VERSION 5.8 ;
BUSBITCHARS "[]" ;
DIVIDERCHAR "/" ;
UNITS
    DATABASE MICRONS 1000 ;
END UNITS

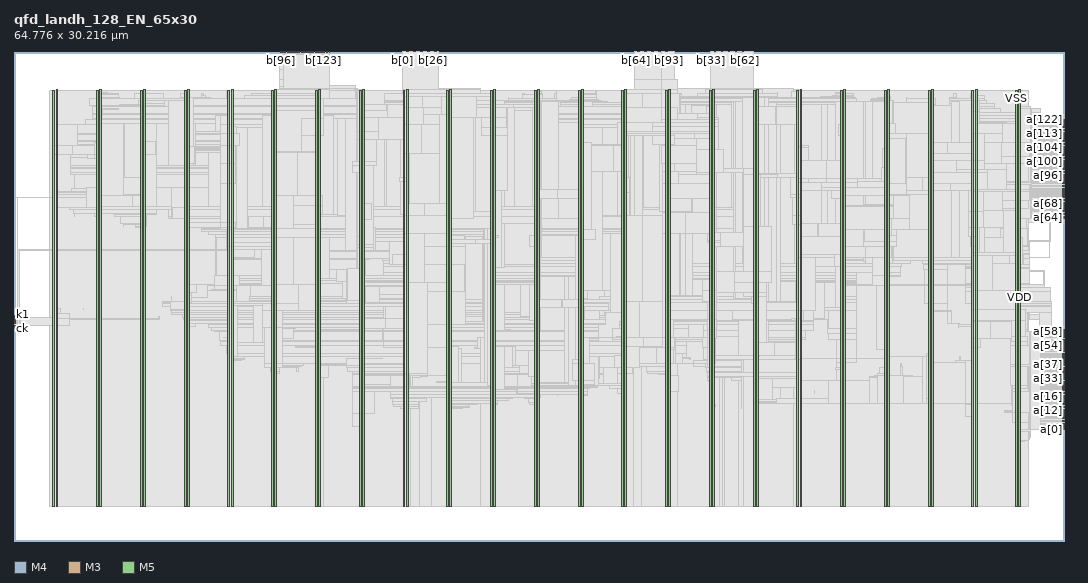
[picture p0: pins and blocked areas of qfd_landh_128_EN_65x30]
MACRO qfd_landh_128_EN_65x30
  FOREIGN qfd_landh_128_EN_65x30 0 0 ;
  CLASS BLOCK ;
  SIZE 64.776 BY 30.216 ;
  PIN a[0]
    DIRECTION INPUT ;
    USE SIGNAL ;
    PORT
      LAYER M4 ;
        RECT  64.692 6.864 64.776 6.888 ;
    END
  END a[0]
  PIN a[100]
    DIRECTION INPUT ;
    USE SIGNAL ;
    PORT
      LAYER M4 ;
        RECT  64.692 23.376 64.776 23.4 ;
    END
  END a[100]
  PIN a[101]
    DIRECTION INPUT ;
    USE SIGNAL ;
    PORT
      LAYER M4 ;
        RECT  64.692 23.472 64.776 23.496 ;
    END
  END a[101]
  PIN a[102]
    DIRECTION INPUT ;
    USE SIGNAL ;
    PORT
      LAYER M4 ;
        RECT  64.692 23.568 64.776 23.592 ;
    END
  END a[102]
  PIN a[103]
    DIRECTION INPUT ;
    USE SIGNAL ;
    PORT
      LAYER M4 ;
        RECT  64.692 23.664 64.776 23.688 ;
    END
  END a[103]
  PIN a[104]
    DIRECTION INPUT ;
    USE SIGNAL ;
    PORT
      LAYER M4 ;
        RECT  64.692 23.76 64.776 23.784 ;
    END
  END a[104]
  PIN a[105]
    DIRECTION INPUT ;
    USE SIGNAL ;
    PORT
      LAYER M4 ;
        RECT  64.692 23.856 64.776 23.88 ;
    END
  END a[105]
  PIN a[106]
    DIRECTION INPUT ;
    USE SIGNAL ;
    PORT
      LAYER M4 ;
        RECT  64.692 23.952 64.776 23.976 ;
    END
  END a[106]
  PIN a[107]
    DIRECTION INPUT ;
    USE SIGNAL ;
    PORT
      LAYER M4 ;
        RECT  64.692 24.048 64.776 24.072 ;
    END
  END a[107]
  PIN a[108]
    DIRECTION INPUT ;
    USE SIGNAL ;
    PORT
      LAYER M4 ;
        RECT  64.692 24.144 64.776 24.168 ;
    END
  END a[108]
  PIN a[109]
    DIRECTION INPUT ;
    USE SIGNAL ;
    PORT
      LAYER M4 ;
        RECT  64.692 24.24 64.776 24.264 ;
    END
  END a[109]
  PIN a[10]
    DIRECTION INPUT ;
    USE SIGNAL ;
    PORT
      LAYER M4 ;
        RECT  64.692 7.824 64.776 7.848 ;
    END
  END a[10]
  PIN a[110]
    DIRECTION INPUT ;
    USE SIGNAL ;
    PORT
      LAYER M4 ;
        RECT  64.692 24.336 64.776 24.36 ;
    END
  END a[110]
  PIN a[111]
    DIRECTION INPUT ;
    USE SIGNAL ;
    PORT
      LAYER M4 ;
        RECT  64.692 24.432 64.776 24.456 ;
    END
  END a[111]
  PIN a[112]
    DIRECTION INPUT ;
    USE SIGNAL ;
    PORT
      LAYER M4 ;
        RECT  64.692 24.528 64.776 24.552 ;
    END
  END a[112]
  PIN a[113]
    DIRECTION INPUT ;
    USE SIGNAL ;
    PORT
      LAYER M4 ;
        RECT  64.692 24.624 64.776 24.648 ;
    END
  END a[113]
  PIN a[114]
    DIRECTION INPUT ;
    USE SIGNAL ;
    PORT
      LAYER M4 ;
        RECT  64.692 24.72 64.776 24.744 ;
    END
  END a[114]
  PIN a[115]
    DIRECTION INPUT ;
    USE SIGNAL ;
    PORT
      LAYER M4 ;
        RECT  64.692 24.816 64.776 24.84 ;
    END
  END a[115]
  PIN a[116]
    DIRECTION INPUT ;
    USE SIGNAL ;
    PORT
      LAYER M4 ;
        RECT  64.692 24.912 64.776 24.936 ;
    END
  END a[116]
  PIN a[117]
    DIRECTION INPUT ;
    USE SIGNAL ;
    PORT
      LAYER M4 ;
        RECT  64.692 25.008 64.776 25.032 ;
    END
  END a[117]
  PIN a[118]
    DIRECTION INPUT ;
    USE SIGNAL ;
    PORT
      LAYER M4 ;
        RECT  64.692 25.104 64.776 25.128 ;
    END
  END a[118]
  PIN a[119]
    DIRECTION INPUT ;
    USE SIGNAL ;
    PORT
      LAYER M4 ;
        RECT  64.692 25.2 64.776 25.224 ;
    END
  END a[119]
  PIN a[11]
    DIRECTION INPUT ;
    USE SIGNAL ;
    PORT
      LAYER M4 ;
        RECT  64.692 7.92 64.776 7.944 ;
    END
  END a[11]
  PIN a[120]
    DIRECTION INPUT ;
    USE SIGNAL ;
    PORT
      LAYER M4 ;
        RECT  64.692 25.296 64.776 25.32 ;
    END
  END a[120]
  PIN a[121]
    DIRECTION INPUT ;
    USE SIGNAL ;
    PORT
      LAYER M4 ;
        RECT  64.692 25.392 64.776 25.416 ;
    END
  END a[121]
  PIN a[122]
    DIRECTION INPUT ;
    USE SIGNAL ;
    PORT
      LAYER M4 ;
        RECT  64.692 25.488 64.776 25.512 ;
    END
  END a[122]
  PIN a[123]
    DIRECTION INPUT ;
    USE SIGNAL ;
    PORT
      LAYER M4 ;
        RECT  64.692 25.584 64.776 25.608 ;
    END
  END a[123]
  PIN a[124]
    DIRECTION INPUT ;
    USE SIGNAL ;
    PORT
      LAYER M4 ;
        RECT  64.692 25.68 64.776 25.704 ;
    END
  END a[124]
  PIN a[125]
    DIRECTION INPUT ;
    USE SIGNAL ;
    PORT
      LAYER M4 ;
        RECT  64.692 25.776 64.776 25.8 ;
    END
  END a[125]
  PIN a[126]
    DIRECTION INPUT ;
    USE SIGNAL ;
    PORT
      LAYER M4 ;
        RECT  64.692 25.872 64.776 25.896 ;
    END
  END a[126]
  PIN a[127]
    DIRECTION INPUT ;
    USE SIGNAL ;
    PORT
      LAYER M4 ;
        RECT  64.692 25.968 64.776 25.992 ;
    END
  END a[127]
  PIN a[12]
    DIRECTION INPUT ;
    USE SIGNAL ;
    PORT
      LAYER M4 ;
        RECT  64.692 8.016 64.776 8.04 ;
    END
  END a[12]
  PIN a[13]
    DIRECTION INPUT ;
    USE SIGNAL ;
    PORT
      LAYER M4 ;
        RECT  64.692 8.112 64.776 8.136 ;
    END
  END a[13]
  PIN a[14]
    DIRECTION INPUT ;
    USE SIGNAL ;
    PORT
      LAYER M4 ;
        RECT  64.692 8.208 64.776 8.232 ;
    END
  END a[14]
  PIN a[15]
    DIRECTION INPUT ;
    USE SIGNAL ;
    PORT
      LAYER M4 ;
        RECT  64.692 8.304 64.776 8.328 ;
    END
  END a[15]
  PIN a[16]
    DIRECTION INPUT ;
    USE SIGNAL ;
    PORT
      LAYER M4 ;
        RECT  64.692 8.4 64.776 8.424 ;
    END
  END a[16]
  PIN a[17]
    DIRECTION INPUT ;
    USE SIGNAL ;
    PORT
      LAYER M4 ;
        RECT  64.692 8.496 64.776 8.52 ;
    END
  END a[17]
  PIN a[18]
    DIRECTION INPUT ;
    USE SIGNAL ;
    PORT
      LAYER M4 ;
        RECT  64.692 8.592 64.776 8.616 ;
    END
  END a[18]
  PIN a[19]
    DIRECTION INPUT ;
    USE SIGNAL ;
    PORT
      LAYER M4 ;
        RECT  64.692 8.688 64.776 8.712 ;
    END
  END a[19]
  PIN a[1]
    DIRECTION INPUT ;
    USE SIGNAL ;
    PORT
      LAYER M4 ;
        RECT  64.692 6.96 64.776 6.984 ;
    END
  END a[1]
  PIN a[20]
    DIRECTION INPUT ;
    USE SIGNAL ;
    PORT
      LAYER M4 ;
        RECT  64.692 8.784 64.776 8.808 ;
    END
  END a[20]
  PIN a[21]
    DIRECTION INPUT ;
    USE SIGNAL ;
    PORT
      LAYER M4 ;
        RECT  64.692 8.88 64.776 8.904 ;
    END
  END a[21]
  PIN a[22]
    DIRECTION INPUT ;
    USE SIGNAL ;
    PORT
      LAYER M4 ;
        RECT  64.692 8.976 64.776 9 ;
    END
  END a[22]
  PIN a[23]
    DIRECTION INPUT ;
    USE SIGNAL ;
    PORT
      LAYER M4 ;
        RECT  64.692 9.072 64.776 9.096 ;
    END
  END a[23]
  PIN a[24]
    DIRECTION INPUT ;
    USE SIGNAL ;
    PORT
      LAYER M4 ;
        RECT  64.692 9.168 64.776 9.192 ;
    END
  END a[24]
  PIN a[25]
    DIRECTION INPUT ;
    USE SIGNAL ;
    PORT
      LAYER M4 ;
        RECT  64.692 9.264 64.776 9.288 ;
    END
  END a[25]
  PIN a[26]
    DIRECTION INPUT ;
    USE SIGNAL ;
    PORT
      LAYER M4 ;
        RECT  64.692 9.36 64.776 9.384 ;
    END
  END a[26]
  PIN a[27]
    DIRECTION INPUT ;
    USE SIGNAL ;
    PORT
      LAYER M4 ;
        RECT  64.692 9.456 64.776 9.48 ;
    END
  END a[27]
  PIN a[28]
    DIRECTION INPUT ;
    USE SIGNAL ;
    PORT
      LAYER M4 ;
        RECT  64.692 9.552 64.776 9.576 ;
    END
  END a[28]
  PIN a[29]
    DIRECTION INPUT ;
    USE SIGNAL ;
    PORT
      LAYER M4 ;
        RECT  64.692 9.648 64.776 9.672 ;
    END
  END a[29]
  PIN a[2]
    DIRECTION INPUT ;
    USE SIGNAL ;
    PORT
      LAYER M4 ;
        RECT  64.692 7.056 64.776 7.08 ;
    END
  END a[2]
  PIN a[30]
    DIRECTION INPUT ;
    USE SIGNAL ;
    PORT
      LAYER M4 ;
        RECT  64.692 9.744 64.776 9.768 ;
    END
  END a[30]
  PIN a[31]
    DIRECTION INPUT ;
    USE SIGNAL ;
    PORT
      LAYER M4 ;
        RECT  64.692 9.84 64.776 9.864 ;
    END
  END a[31]
  PIN a[32]
    DIRECTION INPUT ;
    USE SIGNAL ;
    PORT
      LAYER M4 ;
        RECT  64.692 9.936 64.776 9.96 ;
    END
  END a[32]
  PIN a[33]
    DIRECTION INPUT ;
    USE SIGNAL ;
    PORT
      LAYER M4 ;
        RECT  64.692 10.032 64.776 10.056 ;
    END
  END a[33]
  PIN a[34]
    DIRECTION INPUT ;
    USE SIGNAL ;
    PORT
      LAYER M4 ;
        RECT  64.692 10.128 64.776 10.152 ;
    END
  END a[34]
  PIN a[35]
    DIRECTION INPUT ;
    USE SIGNAL ;
    PORT
      LAYER M4 ;
        RECT  64.692 10.224 64.776 10.248 ;
    END
  END a[35]
  PIN a[36]
    DIRECTION INPUT ;
    USE SIGNAL ;
    PORT
      LAYER M4 ;
        RECT  64.692 10.32 64.776 10.344 ;
    END
  END a[36]
  PIN a[37]
    DIRECTION INPUT ;
    USE SIGNAL ;
    PORT
      LAYER M4 ;
        RECT  64.692 10.416 64.776 10.44 ;
    END
  END a[37]
  PIN a[38]
    DIRECTION INPUT ;
    USE SIGNAL ;
    PORT
      LAYER M4 ;
        RECT  64.692 10.512 64.776 10.536 ;
    END
  END a[38]
  PIN a[39]
    DIRECTION INPUT ;
    USE SIGNAL ;
    PORT
      LAYER M4 ;
        RECT  64.692 10.608 64.776 10.632 ;
    END
  END a[39]
  PIN a[3]
    DIRECTION INPUT ;
    USE SIGNAL ;
    PORT
      LAYER M4 ;
        RECT  64.692 7.152 64.776 7.176 ;
    END
  END a[3]
  PIN a[40]
    DIRECTION INPUT ;
    USE SIGNAL ;
    PORT
      LAYER M4 ;
        RECT  64.692 10.704 64.776 10.728 ;
    END
  END a[40]
  PIN a[41]
    DIRECTION INPUT ;
    USE SIGNAL ;
    PORT
      LAYER M4 ;
        RECT  64.692 10.8 64.776 10.824 ;
    END
  END a[41]
  PIN a[42]
    DIRECTION INPUT ;
    USE SIGNAL ;
    PORT
      LAYER M4 ;
        RECT  64.692 10.896 64.776 10.92 ;
    END
  END a[42]
  PIN a[43]
    DIRECTION INPUT ;
    USE SIGNAL ;
    PORT
      LAYER M4 ;
        RECT  64.692 10.992 64.776 11.016 ;
    END
  END a[43]
  PIN a[44]
    DIRECTION INPUT ;
    USE SIGNAL ;
    PORT
      LAYER M4 ;
        RECT  64.692 11.088 64.776 11.112 ;
    END
  END a[44]
  PIN a[45]
    DIRECTION INPUT ;
    USE SIGNAL ;
    PORT
      LAYER M4 ;
        RECT  64.692 11.184 64.776 11.208 ;
    END
  END a[45]
  PIN a[46]
    DIRECTION INPUT ;
    USE SIGNAL ;
    PORT
      LAYER M4 ;
        RECT  64.692 11.28 64.776 11.304 ;
    END
  END a[46]
  PIN a[47]
    DIRECTION INPUT ;
    USE SIGNAL ;
    PORT
      LAYER M4 ;
        RECT  64.692 11.376 64.776 11.4 ;
    END
  END a[47]
  PIN a[48]
    DIRECTION INPUT ;
    USE SIGNAL ;
    PORT
      LAYER M4 ;
        RECT  64.692 11.472 64.776 11.496 ;
    END
  END a[48]
  PIN a[49]
    DIRECTION INPUT ;
    USE SIGNAL ;
    PORT
      LAYER M4 ;
        RECT  64.692 11.568 64.776 11.592 ;
    END
  END a[49]
  PIN a[4]
    DIRECTION INPUT ;
    USE SIGNAL ;
    PORT
      LAYER M4 ;
        RECT  64.692 7.248 64.776 7.272 ;
    END
  END a[4]
  PIN a[50]
    DIRECTION INPUT ;
    USE SIGNAL ;
    PORT
      LAYER M4 ;
        RECT  64.692 11.664 64.776 11.688 ;
    END
  END a[50]
  PIN a[51]
    DIRECTION INPUT ;
    USE SIGNAL ;
    PORT
      LAYER M4 ;
        RECT  64.692 11.76 64.776 11.784 ;
    END
  END a[51]
  PIN a[52]
    DIRECTION INPUT ;
    USE SIGNAL ;
    PORT
      LAYER M4 ;
        RECT  64.692 11.856 64.776 11.88 ;
    END
  END a[52]
  PIN a[53]
    DIRECTION INPUT ;
    USE SIGNAL ;
    PORT
      LAYER M4 ;
        RECT  64.692 11.952 64.776 11.976 ;
    END
  END a[53]
  PIN a[54]
    DIRECTION INPUT ;
    USE SIGNAL ;
    PORT
      LAYER M4 ;
        RECT  64.692 12.048 64.776 12.072 ;
    END
  END a[54]
  PIN a[55]
    DIRECTION INPUT ;
    USE SIGNAL ;
    PORT
      LAYER M4 ;
        RECT  64.692 12.144 64.776 12.168 ;
    END
  END a[55]
  PIN a[56]
    DIRECTION INPUT ;
    USE SIGNAL ;
    PORT
      LAYER M4 ;
        RECT  64.692 12.24 64.776 12.264 ;
    END
  END a[56]
  PIN a[57]
    DIRECTION INPUT ;
    USE SIGNAL ;
    PORT
      LAYER M4 ;
        RECT  64.692 12.336 64.776 12.36 ;
    END
  END a[57]
  PIN a[58]
    DIRECTION INPUT ;
    USE SIGNAL ;
    PORT
      LAYER M4 ;
        RECT  64.692 12.432 64.776 12.456 ;
    END
  END a[58]
  PIN a[59]
    DIRECTION INPUT ;
    USE SIGNAL ;
    PORT
      LAYER M4 ;
        RECT  64.692 12.528 64.776 12.552 ;
    END
  END a[59]
  PIN a[5]
    DIRECTION INPUT ;
    USE SIGNAL ;
    PORT
      LAYER M4 ;
        RECT  64.692 7.344 64.776 7.368 ;
    END
  END a[5]
  PIN a[60]
    DIRECTION INPUT ;
    USE SIGNAL ;
    PORT
      LAYER M4 ;
        RECT  64.692 12.624 64.776 12.648 ;
    END
  END a[60]
  PIN a[61]
    DIRECTION INPUT ;
    USE SIGNAL ;
    PORT
      LAYER M4 ;
        RECT  64.692 12.72 64.776 12.744 ;
    END
  END a[61]
  PIN a[62]
    DIRECTION INPUT ;
    USE SIGNAL ;
    PORT
      LAYER M4 ;
        RECT  64.692 12.816 64.776 12.84 ;
    END
  END a[62]
  PIN a[63]
    DIRECTION INPUT ;
    USE SIGNAL ;
    PORT
      LAYER M4 ;
        RECT  64.692 12.912 64.776 12.936 ;
    END
  END a[63]
  PIN a[64]
    DIRECTION INPUT ;
    USE SIGNAL ;
    PORT
      LAYER M4 ;
        RECT  64.692 19.92 64.776 19.944 ;
    END
  END a[64]
  PIN a[65]
    DIRECTION INPUT ;
    USE SIGNAL ;
    PORT
      LAYER M4 ;
        RECT  64.692 20.016 64.776 20.04 ;
    END
  END a[65]
  PIN a[66]
    DIRECTION INPUT ;
    USE SIGNAL ;
    PORT
      LAYER M4 ;
        RECT  64.692 20.112 64.776 20.136 ;
    END
  END a[66]
  PIN a[67]
    DIRECTION INPUT ;
    USE SIGNAL ;
    PORT
      LAYER M4 ;
        RECT  64.692 20.208 64.776 20.232 ;
    END
  END a[67]
  PIN a[68]
    DIRECTION INPUT ;
    USE SIGNAL ;
    PORT
      LAYER M4 ;
        RECT  64.692 20.304 64.776 20.328 ;
    END
  END a[68]
  PIN a[69]
    DIRECTION INPUT ;
    USE SIGNAL ;
    PORT
      LAYER M4 ;
        RECT  64.692 20.4 64.776 20.424 ;
    END
  END a[69]
  PIN a[6]
    DIRECTION INPUT ;
    USE SIGNAL ;
    PORT
      LAYER M4 ;
        RECT  64.692 7.44 64.776 7.464 ;
    END
  END a[6]
  PIN a[70]
    DIRECTION INPUT ;
    USE SIGNAL ;
    PORT
      LAYER M4 ;
        RECT  64.692 20.496 64.776 20.52 ;
    END
  END a[70]
  PIN a[71]
    DIRECTION INPUT ;
    USE SIGNAL ;
    PORT
      LAYER M4 ;
        RECT  64.692 20.592 64.776 20.616 ;
    END
  END a[71]
  PIN a[72]
    DIRECTION INPUT ;
    USE SIGNAL ;
    PORT
      LAYER M4 ;
        RECT  64.692 20.688 64.776 20.712 ;
    END
  END a[72]
  PIN a[73]
    DIRECTION INPUT ;
    USE SIGNAL ;
    PORT
      LAYER M4 ;
        RECT  64.692 20.784 64.776 20.808 ;
    END
  END a[73]
  PIN a[74]
    DIRECTION INPUT ;
    USE SIGNAL ;
    PORT
      LAYER M4 ;
        RECT  64.692 20.88 64.776 20.904 ;
    END
  END a[74]
  PIN a[75]
    DIRECTION INPUT ;
    USE SIGNAL ;
    PORT
      LAYER M4 ;
        RECT  64.692 20.976 64.776 21 ;
    END
  END a[75]
  PIN a[76]
    DIRECTION INPUT ;
    USE SIGNAL ;
    PORT
      LAYER M4 ;
        RECT  64.692 21.072 64.776 21.096 ;
    END
  END a[76]
  PIN a[77]
    DIRECTION INPUT ;
    USE SIGNAL ;
    PORT
      LAYER M4 ;
        RECT  64.692 21.168 64.776 21.192 ;
    END
  END a[77]
  PIN a[78]
    DIRECTION INPUT ;
    USE SIGNAL ;
    PORT
      LAYER M4 ;
        RECT  64.692 21.264 64.776 21.288 ;
    END
  END a[78]
  PIN a[79]
    DIRECTION INPUT ;
    USE SIGNAL ;
    PORT
      LAYER M4 ;
        RECT  64.692 21.36 64.776 21.384 ;
    END
  END a[79]
  PIN a[7]
    DIRECTION INPUT ;
    USE SIGNAL ;
    PORT
      LAYER M4 ;
        RECT  64.692 7.536 64.776 7.56 ;
    END
  END a[7]
  PIN a[80]
    DIRECTION INPUT ;
    USE SIGNAL ;
    PORT
      LAYER M4 ;
        RECT  64.692 21.456 64.776 21.48 ;
    END
  END a[80]
  PIN a[81]
    DIRECTION INPUT ;
    USE SIGNAL ;
    PORT
      LAYER M4 ;
        RECT  64.692 21.552 64.776 21.576 ;
    END
  END a[81]
  PIN a[82]
    DIRECTION INPUT ;
    USE SIGNAL ;
    PORT
      LAYER M4 ;
        RECT  64.692 21.648 64.776 21.672 ;
    END
  END a[82]
  PIN a[83]
    DIRECTION INPUT ;
    USE SIGNAL ;
    PORT
      LAYER M4 ;
        RECT  64.692 21.744 64.776 21.768 ;
    END
  END a[83]
  PIN a[84]
    DIRECTION INPUT ;
    USE SIGNAL ;
    PORT
      LAYER M4 ;
        RECT  64.692 21.84 64.776 21.864 ;
    END
  END a[84]
  PIN a[85]
    DIRECTION INPUT ;
    USE SIGNAL ;
    PORT
      LAYER M4 ;
        RECT  64.692 21.936 64.776 21.96 ;
    END
  END a[85]
  PIN a[86]
    DIRECTION INPUT ;
    USE SIGNAL ;
    PORT
      LAYER M4 ;
        RECT  64.692 22.032 64.776 22.056 ;
    END
  END a[86]
  PIN a[87]
    DIRECTION INPUT ;
    USE SIGNAL ;
    PORT
      LAYER M4 ;
        RECT  64.692 22.128 64.776 22.152 ;
    END
  END a[87]
  PIN a[88]
    DIRECTION INPUT ;
    USE SIGNAL ;
    PORT
      LAYER M4 ;
        RECT  64.692 22.224 64.776 22.248 ;
    END
  END a[88]
  PIN a[89]
    DIRECTION INPUT ;
    USE SIGNAL ;
    PORT
      LAYER M4 ;
        RECT  64.692 22.32 64.776 22.344 ;
    END
  END a[89]
  PIN a[8]
    DIRECTION INPUT ;
    USE SIGNAL ;
    PORT
      LAYER M4 ;
        RECT  64.692 7.632 64.776 7.656 ;
    END
  END a[8]
  PIN a[90]
    DIRECTION INPUT ;
    USE SIGNAL ;
    PORT
      LAYER M4 ;
        RECT  64.692 22.416 64.776 22.44 ;
    END
  END a[90]
  PIN a[91]
    DIRECTION INPUT ;
    USE SIGNAL ;
    PORT
      LAYER M4 ;
        RECT  64.692 22.512 64.776 22.536 ;
    END
  END a[91]
  PIN a[92]
    DIRECTION INPUT ;
    USE SIGNAL ;
    PORT
      LAYER M4 ;
        RECT  64.692 22.608 64.776 22.632 ;
    END
  END a[92]
  PIN a[93]
    DIRECTION INPUT ;
    USE SIGNAL ;
    PORT
      LAYER M4 ;
        RECT  64.692 22.704 64.776 22.728 ;
    END
  END a[93]
  PIN a[94]
    DIRECTION INPUT ;
    USE SIGNAL ;
    PORT
      LAYER M4 ;
        RECT  64.692 22.8 64.776 22.824 ;
    END
  END a[94]
  PIN a[95]
    DIRECTION INPUT ;
    USE SIGNAL ;
    PORT
      LAYER M4 ;
        RECT  64.692 22.896 64.776 22.92 ;
    END
  END a[95]
  PIN a[96]
    DIRECTION INPUT ;
    USE SIGNAL ;
    PORT
      LAYER M4 ;
        RECT  64.692 22.992 64.776 23.016 ;
    END
  END a[96]
  PIN a[97]
    DIRECTION INPUT ;
    USE SIGNAL ;
    PORT
      LAYER M4 ;
        RECT  64.692 23.088 64.776 23.112 ;
    END
  END a[97]
  PIN a[98]
    DIRECTION INPUT ;
    USE SIGNAL ;
    PORT
      LAYER M4 ;
        RECT  64.692 23.184 64.776 23.208 ;
    END
  END a[98]
  PIN a[99]
    DIRECTION INPUT ;
    USE SIGNAL ;
    PORT
      LAYER M4 ;
        RECT  64.692 23.28 64.776 23.304 ;
    END
  END a[99]
  PIN a[9]
    DIRECTION INPUT ;
    USE SIGNAL ;
    PORT
      LAYER M4 ;
        RECT  64.692 7.728 64.776 7.752 ;
    END
  END a[9]
  PIN b[0]
    DIRECTION OUTPUT ;
    USE SIGNAL ;
    PORT
      LAYER M3 ;
        RECT  23.94 30.179 23.958 30.216 ;
    END
  END b[0]
  PIN b[100]
    DIRECTION OUTPUT ;
    USE SIGNAL ;
    PORT
      LAYER M5 ;
        RECT  16.848 30.132 16.872 30.216 ;
    END
  END b[100]
  PIN b[101]
    DIRECTION OUTPUT ;
    USE SIGNAL ;
    PORT
      LAYER M5 ;
        RECT  16.944 30.132 16.968 30.216 ;
    END
  END b[101]
  PIN b[102]
    DIRECTION OUTPUT ;
    USE SIGNAL ;
    PORT
      LAYER M5 ;
        RECT  17.04 30.132 17.064 30.216 ;
    END
  END b[102]
  PIN b[103]
    DIRECTION OUTPUT ;
    USE SIGNAL ;
    PORT
      LAYER M5 ;
        RECT  17.136 30.132 17.16 30.216 ;
    END
  END b[103]
  PIN b[104]
    DIRECTION OUTPUT ;
    USE SIGNAL ;
    PORT
      LAYER M5 ;
        RECT  17.232 30.132 17.256 30.216 ;
    END
  END b[104]
  PIN b[105]
    DIRECTION OUTPUT ;
    USE SIGNAL ;
    PORT
      LAYER M5 ;
        RECT  17.328 30.132 17.352 30.216 ;
    END
  END b[105]
  PIN b[106]
    DIRECTION OUTPUT ;
    USE SIGNAL ;
    PORT
      LAYER M5 ;
        RECT  17.424 30.132 17.448 30.216 ;
    END
  END b[106]
  PIN b[107]
    DIRECTION OUTPUT ;
    USE SIGNAL ;
    PORT
      LAYER M5 ;
        RECT  17.52 30.132 17.544 30.216 ;
    END
  END b[107]
  PIN b[108]
    DIRECTION OUTPUT ;
    USE SIGNAL ;
    PORT
      LAYER M5 ;
        RECT  17.616 30.132 17.64 30.216 ;
    END
  END b[108]
  PIN b[109]
    DIRECTION OUTPUT ;
    USE SIGNAL ;
    PORT
      LAYER M5 ;
        RECT  17.712 30.132 17.736 30.216 ;
    END
  END b[109]
  PIN b[10]
    DIRECTION OUTPUT ;
    USE SIGNAL ;
    PORT
      LAYER M3 ;
        RECT  24.66 30.179 24.678 30.216 ;
    END
  END b[10]
  PIN b[110]
    DIRECTION OUTPUT ;
    USE SIGNAL ;
    PORT
      LAYER M5 ;
        RECT  17.808 30.132 17.832 30.216 ;
    END
  END b[110]
  PIN b[111]
    DIRECTION OUTPUT ;
    USE SIGNAL ;
    PORT
      LAYER M5 ;
        RECT  17.904 30.132 17.928 30.216 ;
    END
  END b[111]
  PIN b[112]
    DIRECTION OUTPUT ;
    USE SIGNAL ;
    PORT
      LAYER M5 ;
        RECT  18 30.132 18.024 30.216 ;
    END
  END b[112]
  PIN b[113]
    DIRECTION OUTPUT ;
    USE SIGNAL ;
    PORT
      LAYER M5 ;
        RECT  18.096 30.132 18.12 30.216 ;
    END
  END b[113]
  PIN b[114]
    DIRECTION OUTPUT ;
    USE SIGNAL ;
    PORT
      LAYER M5 ;
        RECT  18.192 30.132 18.216 30.216 ;
    END
  END b[114]
  PIN b[115]
    DIRECTION OUTPUT ;
    USE SIGNAL ;
    PORT
      LAYER M5 ;
        RECT  18.288 30.132 18.312 30.216 ;
    END
  END b[115]
  PIN b[116]
    DIRECTION OUTPUT ;
    USE SIGNAL ;
    PORT
      LAYER M5 ;
        RECT  18.384 30.132 18.408 30.216 ;
    END
  END b[116]
  PIN b[117]
    DIRECTION OUTPUT ;
    USE SIGNAL ;
    PORT
      LAYER M5 ;
        RECT  18.48 30.132 18.504 30.216 ;
    END
  END b[117]
  PIN b[118]
    DIRECTION OUTPUT ;
    USE SIGNAL ;
    PORT
      LAYER M5 ;
        RECT  18.576 30.132 18.6 30.216 ;
    END
  END b[118]
  PIN b[119]
    DIRECTION OUTPUT ;
    USE SIGNAL ;
    PORT
      LAYER M5 ;
        RECT  18.672 30.132 18.696 30.216 ;
    END
  END b[119]
  PIN b[11]
    DIRECTION OUTPUT ;
    USE SIGNAL ;
    PORT
      LAYER M3 ;
        RECT  24.732 30.179 24.75 30.216 ;
    END
  END b[11]
  PIN b[120]
    DIRECTION OUTPUT ;
    USE SIGNAL ;
    PORT
      LAYER M5 ;
        RECT  18.768 30.132 18.792 30.216 ;
    END
  END b[120]
  PIN b[121]
    DIRECTION OUTPUT ;
    USE SIGNAL ;
    PORT
      LAYER M5 ;
        RECT  18.864 30.132 18.888 30.216 ;
    END
  END b[121]
  PIN b[122]
    DIRECTION OUTPUT ;
    USE SIGNAL ;
    PORT
      LAYER M5 ;
        RECT  18.96 30.132 18.984 30.216 ;
    END
  END b[122]
  PIN b[123]
    DIRECTION OUTPUT ;
    USE SIGNAL ;
    PORT
      LAYER M5 ;
        RECT  19.056 30.132 19.08 30.216 ;
    END
  END b[123]
  PIN b[124]
    DIRECTION OUTPUT ;
    USE SIGNAL ;
    PORT
      LAYER M5 ;
        RECT  19.152 30.132 19.176 30.216 ;
    END
  END b[124]
  PIN b[125]
    DIRECTION OUTPUT ;
    USE SIGNAL ;
    PORT
      LAYER M5 ;
        RECT  19.248 30.132 19.272 30.216 ;
    END
  END b[125]
  PIN b[126]
    DIRECTION OUTPUT ;
    USE SIGNAL ;
    PORT
      LAYER M5 ;
        RECT  19.344 30.132 19.368 30.216 ;
    END
  END b[126]
  PIN b[127]
    DIRECTION OUTPUT ;
    USE SIGNAL ;
    PORT
      LAYER M5 ;
        RECT  19.44 30.132 19.464 30.216 ;
    END
  END b[127]
  PIN b[12]
    DIRECTION OUTPUT ;
    USE SIGNAL ;
    PORT
      LAYER M3 ;
        RECT  24.804 30.179 24.822 30.216 ;
    END
  END b[12]
  PIN b[13]
    DIRECTION OUTPUT ;
    USE SIGNAL ;
    PORT
      LAYER M3 ;
        RECT  24.876 30.179 24.894 30.216 ;
    END
  END b[13]
  PIN b[14]
    DIRECTION OUTPUT ;
    USE SIGNAL ;
    PORT
      LAYER M3 ;
        RECT  24.948 30.179 24.966 30.216 ;
    END
  END b[14]
  PIN b[15]
    DIRECTION OUTPUT ;
    USE SIGNAL ;
    PORT
      LAYER M3 ;
        RECT  25.02 30.179 25.038 30.216 ;
    END
  END b[15]
  PIN b[16]
    DIRECTION OUTPUT ;
    USE SIGNAL ;
    PORT
      LAYER M3 ;
        RECT  25.092 30.179 25.11 30.216 ;
    END
  END b[16]
  PIN b[17]
    DIRECTION OUTPUT ;
    USE SIGNAL ;
    PORT
      LAYER M3 ;
        RECT  25.164 30.179 25.182 30.216 ;
    END
  END b[17]
  PIN b[18]
    DIRECTION OUTPUT ;
    USE SIGNAL ;
    PORT
      LAYER M3 ;
        RECT  25.236 30.179 25.254 30.216 ;
    END
  END b[18]
  PIN b[19]
    DIRECTION OUTPUT ;
    USE SIGNAL ;
    PORT
      LAYER M3 ;
        RECT  25.308 30.179 25.326 30.216 ;
    END
  END b[19]
  PIN b[1]
    DIRECTION OUTPUT ;
    USE SIGNAL ;
    PORT
      LAYER M3 ;
        RECT  24.012 30.179 24.03 30.216 ;
    END
  END b[1]
  PIN b[20]
    DIRECTION OUTPUT ;
    USE SIGNAL ;
    PORT
      LAYER M3 ;
        RECT  25.38 30.179 25.398 30.216 ;
    END
  END b[20]
  PIN b[21]
    DIRECTION OUTPUT ;
    USE SIGNAL ;
    PORT
      LAYER M3 ;
        RECT  25.452 30.179 25.47 30.216 ;
    END
  END b[21]
  PIN b[22]
    DIRECTION OUTPUT ;
    USE SIGNAL ;
    PORT
      LAYER M3 ;
        RECT  25.524 30.179 25.542 30.216 ;
    END
  END b[22]
  PIN b[23]
    DIRECTION OUTPUT ;
    USE SIGNAL ;
    PORT
      LAYER M3 ;
        RECT  25.596 30.179 25.614 30.216 ;
    END
  END b[23]
  PIN b[24]
    DIRECTION OUTPUT ;
    USE SIGNAL ;
    PORT
      LAYER M3 ;
        RECT  25.668 30.179 25.686 30.216 ;
    END
  END b[24]
  PIN b[25]
    DIRECTION OUTPUT ;
    USE SIGNAL ;
    PORT
      LAYER M3 ;
        RECT  25.74 30.179 25.758 30.216 ;
    END
  END b[25]
  PIN b[26]
    DIRECTION OUTPUT ;
    USE SIGNAL ;
    PORT
      LAYER M3 ;
        RECT  25.812 30.179 25.83 30.216 ;
    END
  END b[26]
  PIN b[27]
    DIRECTION OUTPUT ;
    USE SIGNAL ;
    PORT
      LAYER M3 ;
        RECT  25.884 30.179 25.902 30.216 ;
    END
  END b[27]
  PIN b[28]
    DIRECTION OUTPUT ;
    USE SIGNAL ;
    PORT
      LAYER M3 ;
        RECT  25.956 30.179 25.974 30.216 ;
    END
  END b[28]
  PIN b[29]
    DIRECTION OUTPUT ;
    USE SIGNAL ;
    PORT
      LAYER M3 ;
        RECT  26.028 30.179 26.046 30.216 ;
    END
  END b[29]
  PIN b[2]
    DIRECTION OUTPUT ;
    USE SIGNAL ;
    PORT
      LAYER M3 ;
        RECT  24.084 30.179 24.102 30.216 ;
    END
  END b[2]
  PIN b[30]
    DIRECTION OUTPUT ;
    USE SIGNAL ;
    PORT
      LAYER M3 ;
        RECT  26.1 30.179 26.118 30.216 ;
    END
  END b[30]
  PIN b[31]
    DIRECTION OUTPUT ;
    USE SIGNAL ;
    PORT
      LAYER M3 ;
        RECT  26.172 30.179 26.19 30.216 ;
    END
  END b[31]
  PIN b[32]
    DIRECTION OUTPUT ;
    USE SIGNAL ;
    PORT
      LAYER M3 ;
        RECT  42.948 30.179 42.966 30.216 ;
    END
  END b[32]
  PIN b[33]
    DIRECTION OUTPUT ;
    USE SIGNAL ;
    PORT
      LAYER M3 ;
        RECT  43.02 30.179 43.038 30.216 ;
    END
  END b[33]
  PIN b[34]
    DIRECTION OUTPUT ;
    USE SIGNAL ;
    PORT
      LAYER M3 ;
        RECT  43.092 30.179 43.11 30.216 ;
    END
  END b[34]
  PIN b[35]
    DIRECTION OUTPUT ;
    USE SIGNAL ;
    PORT
      LAYER M3 ;
        RECT  43.164 30.179 43.182 30.216 ;
    END
  END b[35]
  PIN b[36]
    DIRECTION OUTPUT ;
    USE SIGNAL ;
    PORT
      LAYER M3 ;
        RECT  43.236 30.179 43.254 30.216 ;
    END
  END b[36]
  PIN b[37]
    DIRECTION OUTPUT ;
    USE SIGNAL ;
    PORT
      LAYER M3 ;
        RECT  43.308 30.179 43.326 30.216 ;
    END
  END b[37]
  PIN b[38]
    DIRECTION OUTPUT ;
    USE SIGNAL ;
    PORT
      LAYER M3 ;
        RECT  43.38 30.179 43.398 30.216 ;
    END
  END b[38]
  PIN b[39]
    DIRECTION OUTPUT ;
    USE SIGNAL ;
    PORT
      LAYER M3 ;
        RECT  43.452 30.179 43.47 30.216 ;
    END
  END b[39]
  PIN b[3]
    DIRECTION OUTPUT ;
    USE SIGNAL ;
    PORT
      LAYER M3 ;
        RECT  24.156 30.179 24.174 30.216 ;
    END
  END b[3]
  PIN b[40]
    DIRECTION OUTPUT ;
    USE SIGNAL ;
    PORT
      LAYER M3 ;
        RECT  43.524 30.179 43.542 30.216 ;
    END
  END b[40]
  PIN b[41]
    DIRECTION OUTPUT ;
    USE SIGNAL ;
    PORT
      LAYER M3 ;
        RECT  43.596 30.179 43.614 30.216 ;
    END
  END b[41]
  PIN b[42]
    DIRECTION OUTPUT ;
    USE SIGNAL ;
    PORT
      LAYER M3 ;
        RECT  43.668 30.179 43.686 30.216 ;
    END
  END b[42]
  PIN b[43]
    DIRECTION OUTPUT ;
    USE SIGNAL ;
    PORT
      LAYER M3 ;
        RECT  43.74 30.179 43.758 30.216 ;
    END
  END b[43]
  PIN b[44]
    DIRECTION OUTPUT ;
    USE SIGNAL ;
    PORT
      LAYER M3 ;
        RECT  43.812 30.179 43.83 30.216 ;
    END
  END b[44]
  PIN b[45]
    DIRECTION OUTPUT ;
    USE SIGNAL ;
    PORT
      LAYER M3 ;
        RECT  43.884 30.179 43.902 30.216 ;
    END
  END b[45]
  PIN b[46]
    DIRECTION OUTPUT ;
    USE SIGNAL ;
    PORT
      LAYER M3 ;
        RECT  43.956 30.179 43.974 30.216 ;
    END
  END b[46]
  PIN b[47]
    DIRECTION OUTPUT ;
    USE SIGNAL ;
    PORT
      LAYER M3 ;
        RECT  44.028 30.179 44.046 30.216 ;
    END
  END b[47]
  PIN b[48]
    DIRECTION OUTPUT ;
    USE SIGNAL ;
    PORT
      LAYER M3 ;
        RECT  44.1 30.179 44.118 30.216 ;
    END
  END b[48]
  PIN b[49]
    DIRECTION OUTPUT ;
    USE SIGNAL ;
    PORT
      LAYER M3 ;
        RECT  44.172 30.179 44.19 30.216 ;
    END
  END b[49]
  PIN b[4]
    DIRECTION OUTPUT ;
    USE SIGNAL ;
    PORT
      LAYER M3 ;
        RECT  24.228 30.179 24.246 30.216 ;
    END
  END b[4]
  PIN b[50]
    DIRECTION OUTPUT ;
    USE SIGNAL ;
    PORT
      LAYER M3 ;
        RECT  44.244 30.179 44.262 30.216 ;
    END
  END b[50]
  PIN b[51]
    DIRECTION OUTPUT ;
    USE SIGNAL ;
    PORT
      LAYER M3 ;
        RECT  44.316 30.179 44.334 30.216 ;
    END
  END b[51]
  PIN b[52]
    DIRECTION OUTPUT ;
    USE SIGNAL ;
    PORT
      LAYER M3 ;
        RECT  44.388 30.179 44.406 30.216 ;
    END
  END b[52]
  PIN b[53]
    DIRECTION OUTPUT ;
    USE SIGNAL ;
    PORT
      LAYER M3 ;
        RECT  44.46 30.179 44.478 30.216 ;
    END
  END b[53]
  PIN b[54]
    DIRECTION OUTPUT ;
    USE SIGNAL ;
    PORT
      LAYER M3 ;
        RECT  44.532 30.179 44.55 30.216 ;
    END
  END b[54]
  PIN b[55]
    DIRECTION OUTPUT ;
    USE SIGNAL ;
    PORT
      LAYER M3 ;
        RECT  44.604 30.179 44.622 30.216 ;
    END
  END b[55]
  PIN b[56]
    DIRECTION OUTPUT ;
    USE SIGNAL ;
    PORT
      LAYER M3 ;
        RECT  44.676 30.179 44.694 30.216 ;
    END
  END b[56]
  PIN b[57]
    DIRECTION OUTPUT ;
    USE SIGNAL ;
    PORT
      LAYER M3 ;
        RECT  44.748 30.179 44.766 30.216 ;
    END
  END b[57]
  PIN b[58]
    DIRECTION OUTPUT ;
    USE SIGNAL ;
    PORT
      LAYER M3 ;
        RECT  44.82 30.179 44.838 30.216 ;
    END
  END b[58]
  PIN b[59]
    DIRECTION OUTPUT ;
    USE SIGNAL ;
    PORT
      LAYER M3 ;
        RECT  44.892 30.179 44.91 30.216 ;
    END
  END b[59]
  PIN b[5]
    DIRECTION OUTPUT ;
    USE SIGNAL ;
    PORT
      LAYER M3 ;
        RECT  24.3 30.179 24.318 30.216 ;
    END
  END b[5]
  PIN b[60]
    DIRECTION OUTPUT ;
    USE SIGNAL ;
    PORT
      LAYER M3 ;
        RECT  44.964 30.179 44.982 30.216 ;
    END
  END b[60]
  PIN b[61]
    DIRECTION OUTPUT ;
    USE SIGNAL ;
    PORT
      LAYER M3 ;
        RECT  45.036 30.179 45.054 30.216 ;
    END
  END b[61]
  PIN b[62]
    DIRECTION OUTPUT ;
    USE SIGNAL ;
    PORT
      LAYER M3 ;
        RECT  45.108 30.179 45.126 30.216 ;
    END
  END b[62]
  PIN b[63]
    DIRECTION OUTPUT ;
    USE SIGNAL ;
    PORT
      LAYER M3 ;
        RECT  45.18 30.179 45.198 30.216 ;
    END
  END b[63]
  PIN b[64]
    DIRECTION OUTPUT ;
    USE SIGNAL ;
    PORT
      LAYER M3 ;
        RECT  38.34 30.179 38.358 30.216 ;
    END
  END b[64]
  PIN b[65]
    DIRECTION OUTPUT ;
    USE SIGNAL ;
    PORT
      LAYER M3 ;
        RECT  38.412 30.179 38.43 30.216 ;
    END
  END b[65]
  PIN b[66]
    DIRECTION OUTPUT ;
    USE SIGNAL ;
    PORT
      LAYER M3 ;
        RECT  38.484 30.179 38.502 30.216 ;
    END
  END b[66]
  PIN b[67]
    DIRECTION OUTPUT ;
    USE SIGNAL ;
    PORT
      LAYER M3 ;
        RECT  38.556 30.179 38.574 30.216 ;
    END
  END b[67]
  PIN b[68]
    DIRECTION OUTPUT ;
    USE SIGNAL ;
    PORT
      LAYER M3 ;
        RECT  38.628 30.179 38.646 30.216 ;
    END
  END b[68]
  PIN b[69]
    DIRECTION OUTPUT ;
    USE SIGNAL ;
    PORT
      LAYER M3 ;
        RECT  38.7 30.179 38.718 30.216 ;
    END
  END b[69]
  PIN b[6]
    DIRECTION OUTPUT ;
    USE SIGNAL ;
    PORT
      LAYER M3 ;
        RECT  24.372 30.179 24.39 30.216 ;
    END
  END b[6]
  PIN b[70]
    DIRECTION OUTPUT ;
    USE SIGNAL ;
    PORT
      LAYER M3 ;
        RECT  38.772 30.179 38.79 30.216 ;
    END
  END b[70]
  PIN b[71]
    DIRECTION OUTPUT ;
    USE SIGNAL ;
    PORT
      LAYER M3 ;
        RECT  38.844 30.179 38.862 30.216 ;
    END
  END b[71]
  PIN b[72]
    DIRECTION OUTPUT ;
    USE SIGNAL ;
    PORT
      LAYER M3 ;
        RECT  38.916 30.179 38.934 30.216 ;
    END
  END b[72]
  PIN b[73]
    DIRECTION OUTPUT ;
    USE SIGNAL ;
    PORT
      LAYER M3 ;
        RECT  38.988 30.179 39.006 30.216 ;
    END
  END b[73]
  PIN b[74]
    DIRECTION OUTPUT ;
    USE SIGNAL ;
    PORT
      LAYER M3 ;
        RECT  39.06 30.179 39.078 30.216 ;
    END
  END b[74]
  PIN b[75]
    DIRECTION OUTPUT ;
    USE SIGNAL ;
    PORT
      LAYER M3 ;
        RECT  39.132 30.179 39.15 30.216 ;
    END
  END b[75]
  PIN b[76]
    DIRECTION OUTPUT ;
    USE SIGNAL ;
    PORT
      LAYER M3 ;
        RECT  39.204 30.179 39.222 30.216 ;
    END
  END b[76]
  PIN b[77]
    DIRECTION OUTPUT ;
    USE SIGNAL ;
    PORT
      LAYER M3 ;
        RECT  39.276 30.179 39.294 30.216 ;
    END
  END b[77]
  PIN b[78]
    DIRECTION OUTPUT ;
    USE SIGNAL ;
    PORT
      LAYER M3 ;
        RECT  39.348 30.179 39.366 30.216 ;
    END
  END b[78]
  PIN b[79]
    DIRECTION OUTPUT ;
    USE SIGNAL ;
    PORT
      LAYER M3 ;
        RECT  39.42 30.179 39.438 30.216 ;
    END
  END b[79]
  PIN b[7]
    DIRECTION OUTPUT ;
    USE SIGNAL ;
    PORT
      LAYER M3 ;
        RECT  24.444 30.179 24.462 30.216 ;
    END
  END b[7]
  PIN b[80]
    DIRECTION OUTPUT ;
    USE SIGNAL ;
    PORT
      LAYER M3 ;
        RECT  39.492 30.179 39.51 30.216 ;
    END
  END b[80]
  PIN b[81]
    DIRECTION OUTPUT ;
    USE SIGNAL ;
    PORT
      LAYER M3 ;
        RECT  39.564 30.179 39.582 30.216 ;
    END
  END b[81]
  PIN b[82]
    DIRECTION OUTPUT ;
    USE SIGNAL ;
    PORT
      LAYER M3 ;
        RECT  39.636 30.179 39.654 30.216 ;
    END
  END b[82]
  PIN b[83]
    DIRECTION OUTPUT ;
    USE SIGNAL ;
    PORT
      LAYER M3 ;
        RECT  39.708 30.179 39.726 30.216 ;
    END
  END b[83]
  PIN b[84]
    DIRECTION OUTPUT ;
    USE SIGNAL ;
    PORT
      LAYER M3 ;
        RECT  39.78 30.179 39.798 30.216 ;
    END
  END b[84]
  PIN b[85]
    DIRECTION OUTPUT ;
    USE SIGNAL ;
    PORT
      LAYER M3 ;
        RECT  39.852 30.179 39.87 30.216 ;
    END
  END b[85]
  PIN b[86]
    DIRECTION OUTPUT ;
    USE SIGNAL ;
    PORT
      LAYER M3 ;
        RECT  39.924 30.179 39.942 30.216 ;
    END
  END b[86]
  PIN b[87]
    DIRECTION OUTPUT ;
    USE SIGNAL ;
    PORT
      LAYER M3 ;
        RECT  39.996 30.179 40.014 30.216 ;
    END
  END b[87]
  PIN b[88]
    DIRECTION OUTPUT ;
    USE SIGNAL ;
    PORT
      LAYER M3 ;
        RECT  40.068 30.179 40.086 30.216 ;
    END
  END b[88]
  PIN b[89]
    DIRECTION OUTPUT ;
    USE SIGNAL ;
    PORT
      LAYER M3 ;
        RECT  40.14 30.179 40.158 30.216 ;
    END
  END b[89]
  PIN b[8]
    DIRECTION OUTPUT ;
    USE SIGNAL ;
    PORT
      LAYER M3 ;
        RECT  24.516 30.179 24.534 30.216 ;
    END
  END b[8]
  PIN b[90]
    DIRECTION OUTPUT ;
    USE SIGNAL ;
    PORT
      LAYER M3 ;
        RECT  40.212 30.179 40.23 30.216 ;
    END
  END b[90]
  PIN b[91]
    DIRECTION OUTPUT ;
    USE SIGNAL ;
    PORT
      LAYER M3 ;
        RECT  40.284 30.179 40.302 30.216 ;
    END
  END b[91]
  PIN b[92]
    DIRECTION OUTPUT ;
    USE SIGNAL ;
    PORT
      LAYER M3 ;
        RECT  40.356 30.179 40.374 30.216 ;
    END
  END b[92]
  PIN b[93]
    DIRECTION OUTPUT ;
    USE SIGNAL ;
    PORT
      LAYER M3 ;
        RECT  40.428 30.179 40.446 30.216 ;
    END
  END b[93]
  PIN b[94]
    DIRECTION OUTPUT ;
    USE SIGNAL ;
    PORT
      LAYER M3 ;
        RECT  40.5 30.179 40.518 30.216 ;
    END
  END b[94]
  PIN b[95]
    DIRECTION OUTPUT ;
    USE SIGNAL ;
    PORT
      LAYER M3 ;
        RECT  40.572 30.179 40.59 30.216 ;
    END
  END b[95]
  PIN b[96]
    DIRECTION OUTPUT ;
    USE SIGNAL ;
    PORT
      LAYER M5 ;
        RECT  16.464 30.132 16.488 30.216 ;
    END
  END b[96]
  PIN b[97]
    DIRECTION OUTPUT ;
    USE SIGNAL ;
    PORT
      LAYER M5 ;
        RECT  16.56 30.132 16.584 30.216 ;
    END
  END b[97]
  PIN b[98]
    DIRECTION OUTPUT ;
    USE SIGNAL ;
    PORT
      LAYER M5 ;
        RECT  16.656 30.132 16.68 30.216 ;
    END
  END b[98]
  PIN b[99]
    DIRECTION OUTPUT ;
    USE SIGNAL ;
    PORT
      LAYER M5 ;
        RECT  16.752 30.132 16.776 30.216 ;
    END
  END b[99]
  PIN b[9]
    DIRECTION OUTPUT ;
    USE SIGNAL ;
    PORT
      LAYER M3 ;
        RECT  24.588 30.179 24.606 30.216 ;
    END
  END b[9]
  PIN ck
    DIRECTION INPUT ;
    USE SIGNAL ;
    PORT
      LAYER M4 ;
        RECT  0 13.104 0.084 13.128 ;
    END
  END ck
  PIN ckf
    DIRECTION INPUT ;
    USE SIGNAL ;
    PORT
      LAYER M4 ;
        RECT  0 13.2 0.084 13.224 ;
    END
  END ckf
  PIN ea
    DIRECTION INPUT ;
    USE SIGNAL ;
    PORT
      LAYER M4 ;
        RECT  64.692 13.008 64.776 13.032 ;
    END
  END ea
  PIN fault
    DIRECTION OUTPUT ;
    USE SIGNAL ;
    PORT
      LAYER M4 ;
        RECT  0 13.296 0.084 13.32 ;
    END
  END fault
  PIN k0
    DIRECTION INPUT ;
    USE SIGNAL ;
    PORT
      LAYER M4 ;
        RECT  0 13.392 0.084 13.416 ;
    END
  END k0
  PIN k1
    DIRECTION INPUT ;
    USE SIGNAL ;
    PORT
      LAYER M4 ;
        RECT  0 13.488 0.084 13.512 ;
    END
  END k1
  PIN k2
    DIRECTION INPUT ;
    USE SIGNAL ;
    PORT
      LAYER M4 ;
        RECT  0 13.584 0.084 13.608 ;
    END
  END k2
  PIN rs
    DIRECTION INPUT ;
    USE SIGNAL ;
    PORT
      LAYER M4 ;
        RECT  0 13.68 0.084 13.704 ;
    END
  END rs
  PIN tie_hi
    DIRECTION OUTPUT ;
    USE SIGNAL ;
    PORT
      LAYER M4 ;
        RECT  0 13.776 0.084 13.8 ;
    END
  END tie_hi
  PIN tie_lo
    DIRECTION OUTPUT ;
    USE SIGNAL ;
    PORT
      LAYER M4 ;
        RECT  0 13.872 0.084 13.896 ;
    END
  END tie_lo
  PIN VDD
    DIRECTION INOUT ;
    USE POWER ;
    PORT
      LAYER M5 ;
        RECT  61.992 2.151 62.112 27.833 ;
        RECT  59.292 2.151 59.412 27.833 ;
        RECT  56.592 2.151 56.712 27.833 ;
        RECT  53.892 2.151 54.012 27.833 ;
        RECT  51.192 2.151 51.312 27.833 ;
        RECT  48.492 2.151 48.612 27.833 ;
        RECT  45.792 2.151 45.912 27.833 ;
        RECT  43.092 2.151 43.212 27.833 ;
        RECT  40.392 2.151 40.512 27.833 ;
        RECT  37.692 2.151 37.812 27.833 ;
        RECT  34.992 2.151 35.112 27.833 ;
        RECT  32.292 2.151 32.412 27.833 ;
        RECT  29.592 2.151 29.712 27.833 ;
        RECT  26.892 2.151 27.012 27.833 ;
        RECT  24.192 2.151 24.312 27.833 ;
        RECT  21.492 2.151 21.612 27.833 ;
        RECT  18.792 2.151 18.912 27.833 ;
        RECT  16.092 2.151 16.212 27.833 ;
        RECT  13.392 2.151 13.512 27.833 ;
        RECT  10.692 2.151 10.812 27.833 ;
        RECT  7.992 2.151 8.112 27.833 ;
        RECT  5.292 2.151 5.412 27.833 ;
        RECT  2.592 2.151 2.712 27.833 ;
    END
  END VDD
  PIN VSS
    DIRECTION INOUT ;
    USE GROUND ;
    PORT
      LAYER M5 ;
        RECT  61.8 2.137 61.92 27.819 ;
        RECT  59.1 2.137 59.22 27.819 ;
        RECT  56.4 2.137 56.52 27.819 ;
        RECT  53.7 2.137 53.82 27.819 ;
        RECT  51 2.137 51.12 27.819 ;
        RECT  48.3 2.137 48.42 27.819 ;
        RECT  45.6 2.137 45.72 27.819 ;
        RECT  42.9 2.137 43.02 27.819 ;
        RECT  40.2 2.137 40.32 27.819 ;
        RECT  37.5 2.137 37.62 27.819 ;
        RECT  34.8 2.137 34.92 27.819 ;
        RECT  32.1 2.137 32.22 27.819 ;
        RECT  29.4 2.137 29.52 27.819 ;
        RECT  26.7 2.137 26.82 27.819 ;
        RECT  24 2.137 24.12 27.819 ;
        RECT  21.3 2.137 21.42 27.819 ;
        RECT  18.6 2.137 18.72 27.819 ;
        RECT  15.9 2.137 16.02 27.819 ;
        RECT  13.2 2.137 13.32 27.819 ;
        RECT  10.5 2.137 10.62 27.819 ;
        RECT  7.8 2.137 7.92 27.819 ;
        RECT  5.1 2.137 5.22 27.819 ;
        RECT  2.4 2.137 2.52 27.819 ;
    END
  END VSS
  # OT_OBS_CLOSED layer=M5 d_um=1.536 added=122
  OBS
    LAYER RVTN ;
     RECT  2.16 2.16 62.586 2.295 ;
     RECT  2.16 2.565 62.586 2.835 ;
     RECT  2.16 3.105 62.586 3.375 ;
     RECT  2.16 3.645 62.586 3.915 ;
     RECT  2.16 4.185 62.586 4.455 ;
     RECT  2.16 4.725 62.586 4.995 ;
     RECT  2.16 5.265 62.586 5.535 ;
     RECT  2.16 5.805 62.586 6.075 ;
     RECT  2.16 6.345 62.586 6.615 ;
     RECT  2.16 6.885 62.586 7.155 ;
     RECT  2.16 7.425 62.586 7.695 ;
     RECT  2.16 7.965 62.586 8.235 ;
     RECT  2.16 8.505 62.586 8.775 ;
     RECT  2.16 9.045 62.586 9.315 ;
     RECT  2.16 9.585 62.586 9.855 ;
     RECT  2.16 10.125 62.586 10.395 ;
     RECT  2.16 10.665 62.586 10.935 ;
     RECT  2.16 11.205 62.586 11.475 ;
     RECT  2.16 11.745 62.586 12.015 ;
     RECT  2.16 12.285 62.586 12.555 ;
     RECT  2.16 12.825 62.586 13.095 ;
     RECT  2.16 13.365 62.586 13.635 ;
     RECT  2.16 13.905 62.586 14.175 ;
     RECT  2.16 14.445 62.586 14.715 ;
     RECT  2.16 14.985 62.586 15.255 ;
     RECT  2.16 15.525 62.586 15.795 ;
     RECT  2.16 16.065 62.586 16.335 ;
     RECT  2.16 16.605 62.586 16.875 ;
     RECT  2.16 17.145 62.586 17.415 ;
     RECT  2.16 17.685 62.586 17.955 ;
     RECT  2.16 18.225 62.586 18.495 ;
     RECT  2.16 18.765 62.586 19.035 ;
     RECT  2.16 19.305 62.586 19.575 ;
     RECT  2.16 19.845 62.586 20.115 ;
     RECT  2.16 20.385 62.586 20.655 ;
     RECT  2.16 20.925 62.586 21.195 ;
     RECT  2.16 21.465 62.586 21.735 ;
     RECT  2.16 22.005 62.586 22.275 ;
     RECT  2.16 22.545 62.586 22.815 ;
     RECT  2.16 23.085 62.586 23.355 ;
     RECT  2.16 23.625 62.586 23.895 ;
     RECT  2.16 24.165 62.586 24.435 ;
     RECT  2.16 24.705 62.586 24.975 ;
     RECT  2.16 25.245 62.586 25.515 ;
     RECT  2.16 25.785 62.586 26.055 ;
     RECT  2.16 26.325 62.586 26.595 ;
     RECT  2.16 26.865 62.586 27.135 ;
     RECT  2.16 27.405 62.586 27.675 ;
    LAYER RVTP ;
     RECT  2.16 2.295 62.586 2.565 ;
     RECT  2.16 2.835 62.586 3.105 ;
     RECT  2.16 3.375 62.586 3.645 ;
     RECT  2.16 3.915 62.586 4.185 ;
     RECT  2.16 4.455 62.586 4.725 ;
     RECT  2.16 4.995 62.586 5.265 ;
     RECT  2.16 5.535 62.586 5.805 ;
     RECT  2.16 6.075 62.586 6.345 ;
     RECT  2.16 6.615 62.586 6.885 ;
     RECT  2.16 7.155 62.586 7.425 ;
     RECT  2.16 7.695 62.586 7.965 ;
     RECT  2.16 8.235 62.586 8.505 ;
     RECT  2.16 8.775 62.586 9.045 ;
     RECT  2.16 9.315 62.586 9.585 ;
     RECT  2.16 9.855 62.586 10.125 ;
     RECT  2.16 10.395 62.586 10.665 ;
     RECT  2.16 10.935 62.586 11.205 ;
     RECT  2.16 11.475 62.586 11.745 ;
     RECT  2.16 12.015 62.586 12.285 ;
     RECT  2.16 12.555 62.586 12.825 ;
     RECT  2.16 13.095 62.586 13.365 ;
     RECT  2.16 13.635 62.586 13.905 ;
     RECT  2.16 14.175 62.586 14.445 ;
     RECT  2.16 14.715 62.586 14.985 ;
     RECT  2.16 15.255 62.586 15.525 ;
     RECT  2.16 15.795 62.586 16.065 ;
     RECT  2.16 16.335 62.586 16.605 ;
     RECT  2.16 16.875 62.586 17.145 ;
     RECT  2.16 17.415 62.586 17.685 ;
     RECT  2.16 17.955 62.586 18.225 ;
     RECT  2.16 18.495 62.586 18.765 ;
     RECT  2.16 19.035 62.586 19.305 ;
     RECT  2.16 19.575 62.586 19.845 ;
     RECT  2.16 20.115 62.586 20.385 ;
     RECT  2.16 20.655 62.586 20.925 ;
     RECT  2.16 21.195 62.586 21.465 ;
     RECT  2.16 21.735 62.586 22.005 ;
     RECT  2.16 22.275 62.586 22.545 ;
     RECT  2.16 22.815 62.586 23.085 ;
     RECT  2.16 23.355 62.586 23.625 ;
     RECT  2.16 23.895 62.586 24.165 ;
     RECT  2.16 24.435 62.586 24.705 ;
     RECT  2.16 24.975 62.586 25.245 ;
     RECT  2.16 25.515 62.586 25.785 ;
     RECT  2.16 26.055 62.586 26.325 ;
     RECT  2.16 26.595 62.586 26.865 ;
     RECT  2.16 27.135 62.586 27.405 ;
     RECT  2.16 27.675 62.586 27.81 ;
    LAYER M1 ;
     RECT  2.16 2.151 62.586 27.819 ;
    LAYER M2 ;
     RECT  0.103 13.41 2.16 13.626 ;
     RECT  2.16 2.151 18.751 27.819 ;
     RECT  18.751 2.151 19.067 27.864 ;
     RECT  19.067 2.151 24.223 27.819 ;
     RECT  24.151 29.961 24.295 29.979 ;
     RECT  24.295 29.961 24.367 30.06 ;
     RECT  24.367 29.961 24.395 30.168 ;
     RECT  24.223 2.151 24.439 27.936 ;
     RECT  24.439 2.151 25.007 27.972 ;
     RECT  25.339 29.034 25.475 29.052 ;
     RECT  25.007 2.151 25.735 27.864 ;
     RECT  24.395 30.006 25.979 30.168 ;
     RECT  25.979 30.15 26.087 30.168 ;
     RECT  25.735 2.151 28.787 27.936 ;
     RECT  28.787 2.151 38.191 27.819 ;
     RECT  38.191 2.151 38.723 27.864 ;
     RECT  38.263 30.15 38.839 30.168 ;
     RECT  38.839 30.114 40.063 30.168 ;
     RECT  40.063 30.006 40.163 30.168 ;
     RECT  38.723 2.151 40.279 27.819 ;
     RECT  40.163 30.078 40.379 30.168 ;
     RECT  40.379 30.15 40.739 30.168 ;
     RECT  40.279 2.151 40.919 28.476 ;
     RECT  43.087 30.15 43.159 30.168 ;
     RECT  40.919 2.151 43.519 27.9 ;
     RECT  43.519 2.151 43.735 27.936 ;
     RECT  43.735 2.151 43.835 28.008 ;
     RECT  43.159 29.961 44.267 30.168 ;
     RECT  43.835 2.151 44.671 27.819 ;
     RECT  44.267 30.078 44.915 30.168 ;
     RECT  44.671 2.151 45.031 27.864 ;
     RECT  43.879 29.034 45.203 29.052 ;
     RECT  44.915 30.15 45.599 30.168 ;
     RECT  45.031 2.151 48.083 27.936 ;
     RECT  48.083 2.151 62.586 27.819 ;
     RECT  62.586 13.644 62.663 15.822 ;
     RECT  62.586 16.65 62.663 18.522 ;
     RECT  62.586 6.39 62.699 6.408 ;
     RECT  62.586 23.634 62.699 24.228 ;
     RECT  62.586 8.208 62.807 9.576 ;
     RECT  62.586 11.25 63.059 12.348 ;
     RECT  62.586 10.404 63.311 10.458 ;
     RECT  62.586 22.086 63.311 22.806 ;
     RECT  62.699 23.67 63.311 24.228 ;
     RECT  63.059 11.52 63.347 12.348 ;
     RECT  62.663 14.76 63.347 15.822 ;
     RECT  62.586 26.64 63.347 26.658 ;
     RECT  62.663 13.644 63.383 13.968 ;
     RECT  62.586 25.29 63.383 25.848 ;
     RECT  62.586 19.656 63.491 20.988 ;
     RECT  62.663 16.65 63.563 16.668 ;
     RECT  63.347 14.76 63.671 15.624 ;
     RECT  63.347 11.52 63.887 12.114 ;
     RECT  63.383 13.68 63.887 13.968 ;
     RECT  62.663 17.496 63.887 17.514 ;
     RECT  63.491 19.656 63.887 20.376 ;
     RECT  63.311 22.788 63.887 22.806 ;
     RECT  63.383 25.29 63.887 25.614 ;
     RECT  62.807 8.748 63.923 9.576 ;
     RECT  63.311 10.404 63.923 10.422 ;
     RECT  63.887 12.096 63.923 12.114 ;
     RECT  63.671 15.606 63.923 15.624 ;
     RECT  63.887 19.656 63.923 19.674 ;
     RECT  63.887 25.596 63.923 25.614 ;
     RECT  63.887 13.68 63.959 13.698 ;
     RECT  62.663 18.504 63.959 18.522 ;
     RECT  63.671 14.76 63.995 14.778 ;
     RECT  64.651 9.252 64.751 9.846 ;
     RECT  64.651 21.474 64.751 21.492 ;
     RECT  64.651 22.86 64.751 22.878 ;
     RECT  64.651 24.786 64.751 24.804 ;
    LAYER M3 ;
     RECT  2.415 2.143 2.505 2.413 ;
     RECT  5.115 2.143 5.205 2.413 ;
     RECT  7.815 2.143 7.905 2.413 ;
     RECT  10.515 2.143 10.605 2.413 ;
     RECT  13.215 2.143 13.305 2.413 ;
     RECT  15.915 2.143 16.005 2.413 ;
     RECT  18.615 2.143 18.705 2.413 ;
     RECT  21.315 2.143 21.405 2.413 ;
     RECT  24.015 2.143 24.105 2.413 ;
     RECT  26.715 2.143 26.805 2.413 ;
     RECT  29.415 2.143 29.505 2.413 ;
     RECT  32.115 2.143 32.205 2.413 ;
     RECT  34.815 2.143 34.905 2.413 ;
     RECT  37.515 2.143 37.605 2.413 ;
     RECT  40.215 2.143 40.305 2.413 ;
     RECT  42.915 2.143 43.005 2.413 ;
     RECT  45.615 2.143 45.705 2.413 ;
     RECT  48.315 2.143 48.405 2.413 ;
     RECT  51.015 2.143 51.105 2.413 ;
     RECT  53.715 2.143 53.805 2.413 ;
     RECT  56.415 2.143 56.505 2.413 ;
     RECT  59.115 2.143 59.205 2.413 ;
     RECT  61.815 2.143 61.905 2.413 ;
     RECT  61.815 2.413 62.097 6.115 ;
     RECT  61.815 6.115 62.262 6.151 ;
     RECT  61.815 6.151 62.37 6.385 ;
     RECT  21.315 2.413 21.597 7.051 ;
     RECT  61.815 6.385 62.694 7.243 ;
     RECT  61.815 7.243 62.73 7.435 ;
     RECT  59.115 2.413 59.397 7.699 ;
     RECT  42.915 2.413 43.197 7.771 ;
     RECT  20.88 7.051 21.597 7.861 ;
     RECT  61.815 7.435 62.802 7.897 ;
     RECT  61.452 7.897 62.802 7.933 ;
     RECT  61.092 7.933 62.802 8.011 ;
     RECT  61.092 8.011 63.054 8.069 ;
     RECT  61.596 8.069 63.054 8.107 ;
     RECT  26.715 2.413 26.997 8.167 ;
     RECT  24.015 2.413 24.297 8.203 ;
     RECT  26.715 8.167 27.666 8.251 ;
     RECT  42.876 7.771 43.197 8.275 ;
     RECT  23.832 8.203 24.93 8.311 ;
     RECT  61.596 8.107 63.306 8.395 ;
     RECT  26.715 8.251 28.062 8.401 ;
     RECT  29.415 2.413 29.697 8.401 ;
     RECT  32.115 2.413 32.397 8.401 ;
     RECT  42.876 8.275 43.254 8.429 ;
     RECT  58.716 7.699 59.397 8.429 ;
     RECT  23.4 8.311 24.93 8.437 ;
     RECT  45.615 2.413 45.897 8.491 ;
     RECT  26.715 8.401 28.566 8.509 ;
     RECT  29.415 8.401 29.826 8.509 ;
     RECT  31.788 8.401 32.397 8.545 ;
     RECT  23.364 8.437 24.93 8.581 ;
     RECT  45.615 8.491 46.602 8.581 ;
     RECT  47.34 8.545 47.358 8.581 ;
     RECT  26.715 8.509 29.826 8.671 ;
     RECT  61.596 8.395 63.882 8.683 ;
     RECT  45.615 8.581 47.358 8.699 ;
     RECT  45.615 8.699 47.286 8.735 ;
     RECT  26.715 8.671 30.51 8.779 ;
     RECT  23.364 8.581 25.434 8.815 ;
     RECT  26.715 8.779 30.654 8.815 ;
     RECT  31.752 8.545 32.397 8.815 ;
     RECT  23.256 8.815 25.434 8.851 ;
     RECT  26.715 8.815 30.726 8.851 ;
     RECT  31.464 8.815 32.397 8.851 ;
     RECT  45.615 8.735 45.954 8.969 ;
     RECT  34.815 2.413 35.097 8.977 ;
     RECT  54.72 8.779 54.738 9.005 ;
     RECT  61.596 8.683 63.918 9.005 ;
     RECT  23.256 8.851 32.49 9.013 ;
     RECT  33.516 8.977 33.534 9.013 ;
     RECT  23.256 9.013 33.534 9.049 ;
     RECT  34.815 8.977 35.37 9.049 ;
     RECT  61.632 9.005 63.918 9.113 ;
     RECT  37.515 2.413 37.797 9.121 ;
     RECT  20.88 7.861 22.23 9.247 ;
     RECT  23.256 9.049 35.37 9.247 ;
     RECT  40.215 2.413 40.497 9.247 ;
     RECT  51.015 2.413 51.297 9.247 ;
     RECT  64.728 9.211 64.746 9.247 ;
     RECT  59.115 8.429 59.397 9.259 ;
     RECT  49.392 9.121 49.41 9.275 ;
     RECT  57.996 9.211 58.014 9.293 ;
     RECT  57.852 9.307 57.87 9.347 ;
     RECT  20.88 9.247 35.37 9.391 ;
     RECT  37.26 9.121 37.797 9.391 ;
     RECT  20.88 9.391 35.478 9.481 ;
     RECT  46.764 8.735 47.286 9.481 ;
     RECT  48.315 2.413 48.597 9.481 ;
     RECT  20.88 9.481 35.982 9.509 ;
     RECT  50.94 9.247 51.297 9.517 ;
     RECT  57.528 9.499 57.69 9.545 ;
     RECT  59.04 9.259 59.397 9.553 ;
     RECT  31.932 9.509 35.982 9.595 ;
     RECT  36.756 9.391 37.797 9.595 ;
     RECT  50.256 9.517 51.297 9.629 ;
     RECT  50.688 9.629 51.297 9.653 ;
     RECT  31.932 9.595 37.797 9.689 ;
     RECT  57.672 9.545 57.69 9.689 ;
     RECT  64.656 9.247 64.746 9.851 ;
     RECT  42.876 8.429 43.197 9.859 ;
     RECT  64.656 9.851 64.674 9.869 ;
     RECT  55.26 9.823 55.278 9.883 ;
     RECT  58.716 9.553 59.397 9.883 ;
     RECT  60.156 9.751 60.174 9.883 ;
     RECT  58.716 9.883 60.174 9.923 ;
     RECT  42.84 9.859 43.197 9.931 ;
     RECT  44.856 8.203 44.874 9.931 ;
     RECT  45.615 8.969 45.897 10.021 ;
     RECT  46.764 9.481 48.597 10.021 ;
     RECT  52.92 9.895 52.938 10.021 ;
     RECT  53.715 2.413 53.997 10.021 ;
     RECT  42.768 9.931 43.197 10.057 ;
     RECT  52.92 10.021 53.997 10.075 ;
     RECT  18.615 2.413 18.897 10.093 ;
     RECT  42.768 10.057 43.47 10.093 ;
     RECT  44.244 9.931 44.874 10.093 ;
     RECT  52.776 10.075 53.997 10.121 ;
     RECT  60.12 9.923 60.174 10.121 ;
     RECT  54.72 9.883 55.278 10.123 ;
     RECT  61.632 9.113 63.054 10.123 ;
     RECT  63.864 9.113 63.918 10.123 ;
     RECT  42.768 10.093 44.874 10.129 ;
     RECT  45.615 10.021 48.597 10.129 ;
     RECT  40.215 9.247 41.022 10.193 ;
     RECT  53.064 10.121 53.997 10.193 ;
     RECT  54.72 10.123 55.458 10.193 ;
     RECT  54.72 10.193 54.846 10.205 ;
     RECT  60.264 10.123 60.282 10.229 ;
     RECT  20.88 9.509 31.086 10.291 ;
     RECT  31.932 9.689 36.342 10.291 ;
     RECT  40.215 10.193 40.497 10.291 ;
     RECT  58.716 9.923 59.397 10.291 ;
     RECT  15.915 2.413 16.197 10.327 ;
     RECT  37.26 9.689 37.797 10.327 ;
     RECT  39.744 10.291 40.497 10.327 ;
     RECT  20.88 10.291 36.342 10.349 ;
     RECT  53.28 10.193 53.997 10.355 ;
     RECT  42.768 10.129 48.597 10.391 ;
     RECT  20.88 10.349 31.158 10.435 ;
     RECT  39.06 10.327 40.497 10.435 ;
     RECT  42.768 10.391 44.874 10.435 ;
     RECT  61.632 10.123 63.918 10.463 ;
     RECT  15.915 10.327 16.362 10.471 ;
     RECT  17.424 10.435 17.442 10.471 ;
     RECT  56.415 2.413 56.697 10.561 ;
     RECT  60.444 10.507 60.462 10.561 ;
     RECT  57.852 10.291 59.397 10.589 ;
     RECT  50.724 9.653 51.297 10.597 ;
     RECT  56.196 10.561 56.697 10.597 ;
     RECT  61.632 10.463 63.054 10.603 ;
     RECT  60.444 10.561 60.534 10.625 ;
     RECT  56.088 10.597 56.697 10.637 ;
     RECT  60.516 10.625 60.534 10.637 ;
     RECT  50.688 10.597 51.297 10.697 ;
     RECT  56.196 10.637 56.697 10.697 ;
     RECT  15.84 10.471 16.362 10.699 ;
     RECT  42.732 10.435 44.874 10.699 ;
     RECT  15.48 10.699 16.362 10.705 ;
     RECT  17.424 10.471 17.55 10.705 ;
     RECT  20.592 10.435 31.158 10.705 ;
     RECT  53.388 10.355 53.997 10.733 ;
     RECT  15.48 10.705 17.55 10.741 ;
     RECT  37.26 10.327 38.178 10.741 ;
     RECT  39.024 10.435 40.497 10.741 ;
     RECT  42.696 10.699 44.874 10.741 ;
     RECT  54.72 10.205 54.81 10.769 ;
     RECT  31.932 10.349 36.342 10.795 ;
     RECT  37.224 10.741 40.497 10.795 ;
     RECT  15.48 10.741 17.766 10.831 ;
     RECT  18.615 10.093 19.386 10.831 ;
     RECT  18.615 10.831 19.782 10.867 ;
     RECT  20.52 10.705 31.158 10.867 ;
     RECT  60.624 10.651 60.642 10.895 ;
     RECT  61.38 10.603 63.054 10.895 ;
     RECT  61.488 10.895 63.054 10.925 ;
     RECT  54.72 10.769 54.738 10.931 ;
     RECT  57.96 10.589 59.397 10.931 ;
     RECT  15.48 10.831 17.874 10.975 ;
     RECT  18.615 10.867 31.158 10.975 ;
     RECT  50.724 10.697 51.297 11.011 ;
     RECT  61.56 10.925 63.054 11.039 ;
     RECT  63.864 10.463 63.918 11.083 ;
     RECT  13.215 2.413 13.497 11.137 ;
     RECT  41.94 10.741 44.874 11.165 ;
     RECT  58.104 10.931 59.397 11.165 ;
     RECT  60.732 11.011 60.75 11.165 ;
     RECT  13.215 11.137 14.022 11.173 ;
     RECT  42.516 11.165 44.874 11.209 ;
     RECT  45.615 10.391 48.597 11.209 ;
     RECT  61.596 11.039 63.054 11.273 ;
     RECT  13.215 11.173 14.202 11.281 ;
     RECT  31.932 10.795 40.497 11.281 ;
     RECT  41.688 11.209 41.706 11.281 ;
     RECT  31.932 11.281 41.706 11.309 ;
     RECT  13.215 11.281 14.238 11.371 ;
     RECT  15.48 10.975 31.158 11.371 ;
     RECT  58.356 11.165 58.374 11.399 ;
     RECT  63.864 11.083 63.954 11.467 ;
     RECT  13.215 11.371 31.158 11.551 ;
     RECT  31.932 11.309 41.49 11.551 ;
     RECT  63.288 11.467 63.954 11.563 ;
     RECT  56.304 10.697 56.697 11.579 ;
     RECT  53.715 10.733 53.997 11.821 ;
     RECT  42.516 11.209 48.597 11.947 ;
     RECT  61.596 11.273 62.442 12.043 ;
     RECT  63.288 11.563 63.99 12.043 ;
     RECT  13.104 11.551 41.49 12.091 ;
     RECT  61.596 12.043 63.99 12.091 ;
     RECT  12.744 12.091 41.49 12.317 ;
     RECT  36.9 12.317 41.49 12.325 ;
     RECT  42.48 11.947 48.597 12.325 ;
     RECT  61.524 12.091 63.99 12.325 ;
     RECT  12.744 12.317 36.054 12.361 ;
     RECT  61.488 12.325 63.99 12.361 ;
     RECT  36.9 12.325 48.597 12.451 ;
     RECT  50.724 11.011 52.002 12.451 ;
     RECT  61.452 12.361 63.99 12.509 ;
     RECT  36.9 12.451 48.798 12.557 ;
     RECT  50.22 12.451 52.002 12.829 ;
     RECT  12.672 12.361 36.054 12.901 ;
     RECT  12.348 12.901 36.054 12.991 ;
     RECT  42.516 12.557 48.798 12.991 ;
     RECT  60.696 12.901 60.714 13.019 ;
     RECT  61.452 12.509 62.55 13.063 ;
     RECT  50.184 12.829 52.002 13.091 ;
     RECT  36.9 12.557 41.598 13.127 ;
     RECT  12.168 12.991 36.054 13.171 ;
     RECT  10.515 2.413 10.797 13.261 ;
     RECT  58.248 13.171 58.266 13.261 ;
     RECT  59.115 11.165 59.397 13.261 ;
     RECT  2.415 2.413 2.697 13.291 ;
     RECT  12.024 13.171 36.054 13.333 ;
     RECT  58.248 13.261 59.397 13.361 ;
     RECT  37.332 13.127 41.598 13.369 ;
     RECT  42.516 12.991 49.302 13.369 ;
     RECT  58.248 13.361 58.338 13.405 ;
     RECT  57.6 13.405 58.338 13.433 ;
     RECT  10.515 13.261 11.178 13.441 ;
     RECT  12.024 13.333 36.486 13.441 ;
     RECT  0.108 13.387 0.126 13.483 ;
     RECT  37.332 13.369 49.302 13.559 ;
     RECT  0.108 13.483 0.342 13.613 ;
     RECT  37.515 13.559 49.302 13.627 ;
     RECT  0.108 13.613 0.198 13.631 ;
     RECT  10.515 13.441 36.486 13.639 ;
     RECT  37.515 13.627 49.338 13.675 ;
     RECT  50.184 13.091 50.238 13.675 ;
     RECT  10.44 13.639 36.486 13.801 ;
     RECT  8.928 13.675 8.946 13.865 ;
     RECT  0.18 13.631 0.198 13.901 ;
     RECT  10.368 13.801 36.486 13.981 ;
     RECT  2.415 13.291 3.402 14.009 ;
     RECT  60.948 13.063 62.55 14.071 ;
     RECT  63.288 12.509 63.99 14.071 ;
     RECT  9.72 13.981 36.486 14.107 ;
     RECT  56.415 11.579 56.697 14.179 ;
     RECT  57.6 13.433 57.834 14.179 ;
     RECT  56.415 14.179 57.834 14.207 ;
     RECT  37.515 13.675 50.238 14.215 ;
     RECT  51.015 13.091 52.002 14.215 ;
     RECT  9.72 14.107 36.666 14.245 ;
     RECT  2.415 14.009 2.862 14.369 ;
     RECT  4.284 14.251 4.302 14.369 ;
     RECT  9.684 14.245 36.666 14.449 ;
     RECT  60.948 14.071 63.99 14.449 ;
     RECT  60.444 14.449 63.99 14.521 ;
     RECT  56.415 14.207 57.618 14.647 ;
     RECT  59.115 13.361 59.397 14.647 ;
     RECT  9.144 14.449 36.666 14.675 ;
     RECT  60.12 14.521 63.99 14.675 ;
     RECT  21.312 14.675 36.666 14.711 ;
     RECT  22.536 14.711 36.666 14.731 ;
     RECT  37.515 14.215 52.002 14.731 ;
     RECT  10.515 14.675 20.538 14.747 ;
     RECT  9.144 14.675 9.738 14.765 ;
     RECT  61.092 14.675 63.99 14.783 ;
     RECT  14.544 14.747 20.538 14.861 ;
     RECT  22.536 14.731 52.002 14.909 ;
     RECT  14.544 14.861 20.466 14.945 ;
     RECT  21.312 14.711 21.69 14.945 ;
     RECT  22.536 14.909 35.406 14.945 ;
     RECT  14.544 14.945 20.286 15.053 ;
     RECT  21.312 14.945 21.654 15.053 ;
     RECT  9.72 14.765 9.738 15.089 ;
     RECT  36.144 14.909 52.002 15.089 ;
     RECT  22.536 14.945 33.246 15.215 ;
     RECT  58.716 14.647 59.397 15.403 ;
     RECT  60.12 14.675 60.138 15.403 ;
     RECT  61.092 14.783 63.918 15.403 ;
     RECT  10.515 14.747 13.734 15.449 ;
     RECT  12.204 15.449 13.734 15.521 ;
     RECT  58.716 15.403 63.918 15.629 ;
     RECT  21.315 15.053 21.654 15.763 ;
     RECT  22.536 15.215 33.21 15.763 ;
     RECT  58.716 15.629 63.558 15.827 ;
     RECT  12.384 15.521 13.734 15.871 ;
     RECT  14.616 15.053 20.286 15.871 ;
     RECT  33.984 14.945 35.406 15.871 ;
     RECT  36.432 15.089 52.002 15.871 ;
     RECT  58.716 15.827 62.658 15.899 ;
     RECT  21.315 15.763 33.21 15.961 ;
     RECT  33.984 15.871 52.002 15.961 ;
     RECT  53.208 11.821 53.997 15.961 ;
     RECT  21.315 15.961 52.002 16.027 ;
     RECT  12.384 15.871 20.286 16.069 ;
     RECT  21.06 16.027 52.002 16.069 ;
     RECT  12.384 16.069 52.002 16.169 ;
     RECT  53.136 15.961 53.997 16.303 ;
     RECT  53.136 16.303 54.702 16.375 ;
     RECT  12.384 16.169 12.474 16.397 ;
     RECT  13.215 16.169 52.002 16.403 ;
     RECT  22.824 16.403 52.002 16.573 ;
     RECT  52.992 16.375 54.702 16.573 ;
     RECT  63.54 15.827 63.558 16.673 ;
     RECT  56.196 14.647 57.618 16.771 ;
     RECT  58.716 15.899 59.397 16.807 ;
     RECT  60.12 15.899 62.658 16.807 ;
     RECT  58.716 16.807 62.658 16.871 ;
     RECT  22.824 16.573 54.702 16.915 ;
     RECT  58.716 16.871 59.886 16.943 ;
     RECT  56.124 16.771 57.618 17.041 ;
     RECT  58.716 16.943 59.397 17.041 ;
     RECT  56.124 17.041 59.397 17.113 ;
     RECT  22.824 16.915 54.738 17.117 ;
     RECT  30.78 17.117 54.738 17.149 ;
     RECT  22.824 17.117 30.042 17.311 ;
     RECT  30.78 17.149 55.314 17.311 ;
     RECT  56.052 17.113 59.397 17.311 ;
     RECT  13.215 16.403 21.69 17.347 ;
     RECT  13.215 17.347 21.834 17.383 ;
     RECT  13.215 17.383 21.906 17.419 ;
     RECT  22.752 17.311 30.042 17.419 ;
     RECT  60.84 16.871 62.658 17.659 ;
     RECT  60.228 17.659 62.658 17.755 ;
     RECT  13.215 17.419 30.042 17.887 ;
     RECT  30.78 17.311 59.397 17.887 ;
     RECT  60.192 17.755 62.658 17.915 ;
     RECT  13.215 17.887 59.397 17.951 ;
     RECT  58.716 17.951 59.397 17.995 ;
     RECT  13.215 17.951 57.726 18.149 ;
     RECT  58.716 17.995 59.454 18.149 ;
     RECT  13.215 18.149 57.618 18.185 ;
     RECT  60.228 17.915 62.586 18.185 ;
     RECT  60.84 18.185 62.586 18.257 ;
     RECT  13.215 18.185 57.546 18.419 ;
     RECT  63.864 17.491 63.882 18.499 ;
     RECT  52.632 18.419 57.546 18.563 ;
     RECT  12.456 16.397 12.474 18.733 ;
     RECT  13.215 18.419 51.822 18.733 ;
     RECT  52.632 18.563 57.222 18.749 ;
     RECT  58.716 18.149 59.397 18.797 ;
     RECT  12.456 18.733 51.822 18.931 ;
     RECT  12.024 18.931 51.822 19.111 ;
     RECT  58.896 18.797 59.397 19.201 ;
     RECT  11.556 19.111 51.822 19.229 ;
     RECT  52.668 18.749 57.222 19.229 ;
     RECT  11.556 19.229 14.634 19.265 ;
     RECT  15.372 19.229 51.822 19.301 ;
     RECT  60.84 18.257 62.55 19.301 ;
     RECT  7.815 2.413 8.097 19.345 ;
     RECT  10.515 15.449 10.797 19.345 ;
     RECT  11.556 19.265 14.454 19.345 ;
     RECT  52.668 19.229 54.99 19.373 ;
     RECT  7.524 19.345 8.097 19.381 ;
     RECT  55.728 19.229 57.222 19.381 ;
     RECT  6.732 19.381 6.75 19.507 ;
     RECT  7.524 19.381 8.154 19.507 ;
     RECT  6.732 19.507 8.154 19.615 ;
     RECT  55.728 19.381 57.51 19.679 ;
     RECT  10.515 19.345 14.454 19.885 ;
     RECT  9.756 19.885 14.454 19.921 ;
     RECT  52.74 19.373 54.99 19.963 ;
     RECT  55.728 19.679 57.438 19.963 ;
     RECT  5.115 2.413 5.397 20.011 ;
     RECT  6.552 19.615 8.154 20.011 ;
     RECT  9.504 19.921 14.454 20.011 ;
     RECT  15.372 19.301 51.786 20.011 ;
     RECT  6.3 20.011 8.154 20.047 ;
     RECT  58.896 19.201 59.454 20.047 ;
     RECT  6.192 20.047 8.154 20.119 ;
     RECT  3.744 20.011 3.762 20.191 ;
     RECT  4.968 20.011 5.397 20.191 ;
     RECT  6.192 20.119 8.766 20.191 ;
     RECT  58.284 20.047 59.454 20.191 ;
     RECT  60.84 19.301 62.478 20.191 ;
     RECT  58.284 20.191 62.478 20.219 ;
     RECT  58.788 20.219 62.478 20.309 ;
     RECT  63.864 18.499 63.954 20.425 ;
     RECT  3.672 20.191 8.766 20.461 ;
     RECT  9.504 20.011 51.786 20.461 ;
     RECT  63.288 20.425 63.954 20.525 ;
     RECT  52.74 19.963 57.438 20.551 ;
     RECT  52.56 20.551 57.438 20.587 ;
     RECT  3.42 20.461 51.786 20.683 ;
     RECT  52.56 20.587 57.834 20.683 ;
     RECT  63.288 20.525 63.882 20.717 ;
     RECT  2.415 14.369 2.697 20.857 ;
     RECT  3.42 20.683 57.834 20.857 ;
     RECT  63.468 20.717 63.882 20.993 ;
     RECT  2.415 20.857 57.834 21.001 ;
     RECT  58.788 20.309 59.454 21.001 ;
     RECT  63.864 20.993 63.882 21.005 ;
     RECT  60.228 20.309 62.478 21.211 ;
     RECT  2.415 21.001 59.454 21.355 ;
     RECT  64.656 21.451 64.674 21.469 ;
     RECT  64.656 21.469 64.746 21.497 ;
     RECT  2.415 21.355 59.49 21.505 ;
     RECT  60.228 21.211 62.73 21.505 ;
     RECT  2.415 21.505 62.73 21.533 ;
     RECT  64.728 21.497 64.746 21.533 ;
     RECT  3.528 21.533 62.73 21.731 ;
     RECT  3.708 21.731 62.73 21.767 ;
     RECT  52.812 21.767 62.73 21.839 ;
     RECT  58.32 21.839 62.73 21.931 ;
     RECT  58.32 21.931 62.838 22.027 ;
     RECT  52.812 21.839 57.474 22.109 ;
     RECT  58.32 22.027 63.306 22.267 ;
     RECT  58.32 22.267 64.026 22.577 ;
     RECT  3.708 21.767 52.002 22.621 ;
     RECT  52.812 22.109 57.33 22.621 ;
     RECT  58.32 22.577 62.838 22.733 ;
     RECT  3.456 22.621 57.33 22.739 ;
     RECT  63.864 22.577 64.026 22.843 ;
     RECT  63.864 22.843 64.746 22.883 ;
     RECT  63.864 22.883 64.674 22.925 ;
     RECT  3.492 22.739 57.33 22.981 ;
     RECT  3.492 22.981 57.366 23.017 ;
     RECT  3.492 23.017 57.51 23.161 ;
     RECT  58.32 22.733 62.73 23.161 ;
     RECT  63.864 22.925 64.026 23.213 ;
     RECT  3.492 23.161 62.73 23.665 ;
     RECT  63.864 23.213 63.882 23.665 ;
     RECT  3.492 23.665 63.882 24.091 ;
     RECT  3.492 24.091 63.918 24.133 ;
     RECT  2.415 21.533 2.697 24.241 ;
     RECT  3.42 24.133 63.918 24.241 ;
     RECT  2.415 24.241 63.918 24.269 ;
     RECT  2.415 24.269 62.982 24.359 ;
     RECT  2.415 24.359 3.042 24.365 ;
     RECT  3.888 24.359 62.982 24.461 ;
     RECT  3.888 24.461 57.33 24.665 ;
     RECT  3.888 24.665 57.006 24.737 ;
     RECT  64.728 24.763 64.746 24.781 ;
     RECT  64.656 24.781 64.746 24.809 ;
     RECT  64.656 24.809 64.674 24.845 ;
     RECT  58.284 24.461 62.982 25.003 ;
     RECT  63.9 24.269 63.918 25.003 ;
     RECT  3.888 24.737 56.862 25.079 ;
     RECT  3.888 25.079 55.026 25.169 ;
     RECT  58.284 25.003 63.918 25.205 ;
     RECT  3.888 25.169 54.918 25.675 ;
     RECT  3.672 25.675 54.918 25.715 ;
     RECT  58.392 25.205 63.918 25.901 ;
     RECT  4.392 25.715 54.918 26.015 ;
     RECT  4.824 26.015 54.918 26.095 ;
     RECT  55.8 25.079 56.862 26.095 ;
     RECT  58.392 25.901 63.342 26.095 ;
     RECT  58.356 26.095 63.342 26.257 ;
     RECT  4.824 26.095 56.862 26.299 ;
     RECT  4.824 26.299 57.15 26.393 ;
     RECT  58.248 26.257 63.342 26.429 ;
     RECT  61.815 26.429 63.342 26.663 ;
     RECT  58.248 26.429 60.858 26.699 ;
     RECT  61.815 26.663 62.73 26.717 ;
     RECT  4.824 26.393 56.862 26.789 ;
     RECT  61.815 26.717 62.37 26.789 ;
     RECT  58.248 26.699 60.462 26.797 ;
     RECT  61.815 26.789 62.262 26.825 ;
     RECT  57.888 26.797 60.462 26.827 ;
     RECT  4.824 26.789 21.597 26.869 ;
     RECT  22.86 26.789 56.862 26.909 ;
     RECT  57.708 26.827 60.462 26.969 ;
     RECT  22.86 26.909 54.27 27.059 ;
     RECT  22.86 27.059 36.594 27.095 ;
     RECT  37.515 27.059 54.27 27.101 ;
     RECT  22.86 27.095 36.378 27.131 ;
     RECT  52.812 27.101 54.27 27.197 ;
     RECT  22.86 27.131 36.27 27.203 ;
     RECT  57.708 26.969 59.994 27.203 ;
     RECT  34.272 27.203 36.054 27.239 ;
     RECT  52.812 27.197 54.09 27.239 ;
     RECT  4.644 26.869 21.597 27.329 ;
     RECT  30.492 27.203 33.498 27.329 ;
     RECT  37.515 27.101 52.002 27.329 ;
     RECT  52.884 27.239 54.09 27.329 ;
     RECT  55.044 26.909 56.862 27.329 ;
     RECT  57.708 27.203 59.886 27.329 ;
     RECT  10.296 27.329 12.114 27.341 ;
     RECT  11.592 27.341 12.114 27.352 ;
     RECT  5.115 27.329 6.534 27.365 ;
     RECT  30.492 27.329 30.51 27.365 ;
     RECT  34.38 27.239 35.91 27.365 ;
     RECT  37.515 27.329 51.894 27.365 ;
     RECT  53.244 27.329 54.09 27.365 ;
     RECT  55.044 27.329 55.062 27.365 ;
     RECT  57.708 27.329 58.158 27.365 ;
     RECT  37.515 27.365 47.106 27.401 ;
     RECT  49.752 27.365 51.786 27.401 ;
     RECT  53.715 27.365 54.09 27.401 ;
     RECT  14.22 27.329 21.597 27.473 ;
     RECT  59.004 27.329 59.886 27.473 ;
     RECT  11.592 27.352 11.79 27.509 ;
     RECT  50.508 27.401 51.786 27.509 ;
     RECT  2.415 24.365 2.697 27.557 ;
     RECT  5.115 27.365 6.426 27.557 ;
     RECT  31.356 27.329 32.598 27.557 ;
     RECT  34.815 27.365 35.91 27.557 ;
     RECT  37.515 27.401 41.202 27.557 ;
     RECT  53.715 27.401 53.997 27.557 ;
     RECT  56.415 27.329 56.697 27.557 ;
     RECT  61.815 26.825 62.097 27.557 ;
     RECT  5.256 27.557 6.426 27.599 ;
     RECT  11.592 27.509 11.718 27.599 ;
     RECT  14.652 27.473 21.597 27.599 ;
     RECT  22.86 27.203 29.697 27.599 ;
     RECT  31.356 27.557 31.482 27.599 ;
     RECT  32.307 27.557 32.598 27.599 ;
     RECT  33.372 27.329 33.498 27.599 ;
     RECT  35.007 27.557 35.91 27.599 ;
     RECT  37.707 27.557 41.202 27.599 ;
     RECT  42.156 27.401 47.106 27.599 ;
     RECT  50.688 27.509 51.786 27.599 ;
     RECT  57.96 27.365 58.158 27.599 ;
     RECT  37.707 27.599 41.058 27.629 ;
     RECT  5.307 27.599 6.318 27.635 ;
     RECT  7.452 27.329 9.198 27.635 ;
     RECT  10.296 27.341 10.797 27.635 ;
     RECT  11.592 27.599 11.61 27.635 ;
     RECT  14.652 27.599 14.67 27.635 ;
     RECT  22.86 27.599 22.878 27.635 ;
     RECT  23.94 27.599 29.697 27.635 ;
     RECT  31.356 27.599 31.374 27.635 ;
     RECT  50.688 27.599 51.642 27.635 ;
     RECT  57.96 27.599 57.978 27.635 ;
     RECT  59.004 27.473 59.454 27.635 ;
     RECT  5.307 27.635 5.742 27.671 ;
     RECT  47.088 27.599 47.106 27.671 ;
     RECT  50.688 27.635 51.297 27.671 ;
     RECT  59.307 27.635 59.454 27.671 ;
     RECT  13.14 27.329 13.497 27.707 ;
     RECT  47.952 27.365 48.597 27.707 ;
     RECT  32.307 27.599 32.526 27.743 ;
     RECT  33.48 27.599 33.498 27.743 ;
     RECT  35.892 27.599 35.91 27.743 ;
     RECT  2.607 27.557 2.697 27.827 ;
     RECT  5.307 27.671 5.397 27.827 ;
     RECT  8.007 27.635 8.097 27.827 ;
     RECT  10.707 27.635 10.797 27.827 ;
     RECT  13.407 27.707 13.497 27.827 ;
     RECT  16.107 27.599 21.597 27.827 ;
     RECT  23.94 27.635 28.782 27.827 ;
     RECT  29.607 27.635 29.697 27.827 ;
     RECT  32.307 27.743 32.397 27.827 ;
     RECT  35.007 27.599 35.097 27.827 ;
     RECT  37.707 27.629 40.914 27.827 ;
     RECT  48.06 27.707 48.597 27.827 ;
     RECT  51.207 27.671 51.297 27.827 ;
     RECT  53.907 27.557 53.997 27.827 ;
     RECT  56.607 27.557 56.697 27.827 ;
     RECT  59.307 27.671 59.397 27.827 ;
     RECT  62.007 27.557 62.097 27.827 ;
     RECT  27.684 27.827 28.782 27.869 ;
     RECT  38.196 27.827 40.914 27.869 ;
     RECT  42.66 27.599 46.17 27.869 ;
     RECT  28.224 27.869 28.782 27.905 ;
     RECT  42.66 27.869 45.594 27.905 ;
     RECT  16.38 27.827 21.186 27.917 ;
     RECT  28.764 27.905 28.782 27.941 ;
     RECT  48.06 27.827 48.078 27.941 ;
     RECT  16.38 27.917 21.078 28.013 ;
     RECT  16.38 28.013 19.962 28.061 ;
     RECT  21.06 28.013 21.078 28.109 ;
     RECT  16.38 28.061 19.422 28.445 ;
     RECT  38.268 27.869 40.914 28.481 ;
     RECT  16.38 28.445 19.206 28.493 ;
     RECT  16.38 28.493 17.658 29.069 ;
     RECT  16.38 29.069 17.406 30.077 ;
     RECT  16.452 30.077 17.298 30.125 ;
     RECT  38.268 28.481 40.734 30.173 ;
     RECT  42.948 27.905 45.594 30.173 ;
     RECT  23.94 27.827 26.19 30.179 ;
     RECT  23.958 30.179 24.012 30.204 ;
     RECT  24.03 30.179 24.084 30.204 ;
     RECT  24.102 30.179 24.156 30.204 ;
     RECT  24.174 30.179 24.228 30.204 ;
     RECT  24.246 30.179 24.3 30.204 ;
     RECT  24.318 30.179 24.372 30.204 ;
     RECT  24.39 30.179 24.444 30.204 ;
     RECT  24.462 30.179 24.516 30.204 ;
     RECT  24.534 30.179 24.588 30.204 ;
     RECT  24.606 30.179 24.66 30.204 ;
     RECT  24.678 30.179 24.732 30.204 ;
     RECT  24.75 30.179 24.804 30.204 ;
     RECT  24.822 30.179 24.876 30.204 ;
     RECT  24.894 30.179 24.948 30.204 ;
     RECT  24.966 30.179 25.02 30.204 ;
     RECT  25.038 30.179 25.092 30.204 ;
     RECT  25.11 30.179 25.164 30.204 ;
     RECT  25.182 30.179 25.236 30.204 ;
     RECT  25.254 30.179 25.308 30.204 ;
     RECT  25.326 30.179 25.38 30.204 ;
     RECT  25.398 30.179 25.452 30.204 ;
     RECT  25.47 30.179 25.524 30.204 ;
     RECT  25.542 30.179 25.596 30.204 ;
     RECT  25.614 30.179 25.668 30.204 ;
     RECT  25.686 30.179 25.74 30.204 ;
     RECT  25.758 30.179 25.812 30.204 ;
     RECT  25.83 30.179 25.884 30.204 ;
     RECT  25.902 30.179 25.956 30.204 ;
     RECT  25.974 30.179 26.028 30.204 ;
     RECT  26.046 30.179 26.1 30.204 ;
     RECT  26.118 30.179 26.172 30.204 ;
     RECT  38.34 30.173 40.59 30.179 ;
     RECT  38.358 30.179 38.412 30.204 ;
     RECT  38.43 30.179 38.484 30.204 ;
     RECT  38.502 30.179 38.556 30.204 ;
     RECT  38.574 30.179 38.628 30.204 ;
     RECT  38.646 30.179 38.7 30.204 ;
     RECT  38.718 30.179 38.772 30.204 ;
     RECT  38.79 30.179 38.844 30.204 ;
     RECT  38.862 30.179 38.916 30.204 ;
     RECT  38.934 30.179 38.988 30.204 ;
     RECT  39.006 30.179 39.06 30.204 ;
     RECT  39.078 30.179 39.132 30.204 ;
     RECT  39.15 30.179 39.204 30.204 ;
     RECT  39.222 30.179 39.276 30.204 ;
     RECT  39.294 30.179 39.348 30.204 ;
     RECT  39.366 30.179 39.42 30.204 ;
     RECT  39.438 30.179 39.492 30.204 ;
     RECT  39.51 30.179 39.564 30.204 ;
     RECT  39.582 30.179 39.636 30.204 ;
     RECT  39.654 30.179 39.708 30.204 ;
     RECT  39.726 30.179 39.78 30.204 ;
     RECT  39.798 30.179 39.852 30.204 ;
     RECT  39.87 30.179 39.924 30.204 ;
     RECT  39.942 30.179 39.996 30.204 ;
     RECT  40.014 30.179 40.068 30.204 ;
     RECT  40.086 30.179 40.14 30.204 ;
     RECT  40.158 30.179 40.212 30.204 ;
     RECT  40.23 30.179 40.284 30.204 ;
     RECT  40.302 30.179 40.356 30.204 ;
     RECT  40.374 30.179 40.428 30.204 ;
     RECT  40.446 30.179 40.5 30.204 ;
     RECT  40.518 30.179 40.572 30.204 ;
     RECT  42.948 30.173 45.198 30.179 ;
     RECT  42.966 30.179 43.02 30.204 ;
     RECT  43.038 30.179 43.092 30.204 ;
     RECT  43.11 30.179 43.164 30.204 ;
     RECT  43.182 30.179 43.236 30.204 ;
     RECT  43.254 30.179 43.308 30.204 ;
     RECT  43.326 30.179 43.38 30.204 ;
     RECT  43.398 30.179 43.452 30.204 ;
     RECT  43.47 30.179 43.524 30.204 ;
     RECT  43.542 30.179 43.596 30.204 ;
     RECT  43.614 30.179 43.668 30.204 ;
     RECT  43.686 30.179 43.74 30.204 ;
     RECT  43.758 30.179 43.812 30.204 ;
     RECT  43.83 30.179 43.884 30.204 ;
     RECT  43.902 30.179 43.956 30.204 ;
     RECT  43.974 30.179 44.028 30.204 ;
     RECT  44.046 30.179 44.1 30.204 ;
     RECT  44.118 30.179 44.172 30.204 ;
     RECT  44.19 30.179 44.244 30.204 ;
     RECT  44.262 30.179 44.316 30.204 ;
     RECT  44.334 30.179 44.388 30.204 ;
     RECT  44.406 30.179 44.46 30.204 ;
     RECT  44.478 30.179 44.532 30.204 ;
     RECT  44.55 30.179 44.604 30.204 ;
     RECT  44.622 30.179 44.676 30.204 ;
     RECT  44.694 30.179 44.748 30.204 ;
     RECT  44.766 30.179 44.82 30.204 ;
     RECT  44.838 30.179 44.892 30.204 ;
     RECT  44.91 30.179 44.964 30.204 ;
     RECT  44.982 30.179 45.036 30.204 ;
     RECT  45.054 30.179 45.108 30.204 ;
     RECT  45.126 30.179 45.18 30.204 ;
    LAYER M4 ;
     RECT  0.084 13.104 0.209 13.128 ;
     RECT  0.06 13.128 0.209 13.2 ;
     RECT  0.084 13.2 0.209 13.224 ;
     RECT  0.06 13.224 0.209 13.296 ;
     RECT  0.084 13.296 0.209 13.32 ;
     RECT  0.06 13.32 0.209 13.392 ;
     RECT  0.084 13.392 0.209 13.416 ;
     RECT  0.06 13.416 0.209 13.488 ;
     RECT  0.084 13.488 0.209 13.512 ;
     RECT  0.06 13.512 0.209 13.584 ;
     RECT  0.084 13.584 0.209 13.608 ;
     RECT  0.06 13.608 0.209 13.68 ;
     RECT  0.084 13.68 0.209 13.704 ;
     RECT  0.06 13.704 0.209 13.776 ;
     RECT  0.084 13.776 0.209 13.8 ;
     RECT  0.06 13.8 0.209 13.872 ;
     RECT  0.084 13.872 0.209 13.896 ;
     RECT  0.209 13.104 0.227 13.8 ;
     RECT  0.227 13.2 0.371 13.8 ;
     RECT  0.371 13.296 2.408 13.8 ;
     RECT  0.325 17.952 2.408 17.976 ;
     RECT  0.181 21.168 2.408 21.192 ;
     RECT  2.408 2.148 2.512 27.552 ;
     RECT  2.512 2.418 2.6 27.552 ;
     RECT  2.6 2.418 2.704 27.822 ;
     RECT  2.704 13.296 3.413 13.704 ;
     RECT  2.704 20.544 4.453 21.192 ;
     RECT  2.704 23.856 4.561 24.36 ;
     RECT  4.561 23.568 4.94 24.36 ;
     RECT  2.704 25.68 5.065 25.704 ;
     RECT  3.413 13.68 5.108 13.704 ;
     RECT  2.704 17.952 5.108 17.976 ;
     RECT  4.453 20.544 5.108 21.816 ;
     RECT  4.94 23.568 5.108 24.6 ;
     RECT  5.065 25.68 5.108 26.28 ;
     RECT  5.108 2.148 5.212 27.552 ;
     RECT  5.212 2.418 5.3 27.552 ;
     RECT  5.3 2.418 5.404 27.822 ;
     RECT  5.404 26.256 5.465 26.664 ;
     RECT  5.465 26.64 6.437 26.664 ;
     RECT  5.404 23.568 6.577 23.976 ;
     RECT  5.404 20.64 7.292 21.816 ;
     RECT  6.577 23.568 7.513 24.408 ;
     RECT  6.505 26.928 7.693 26.952 ;
     RECT  5.404 13.68 7.808 13.704 ;
     RECT  5.404 17.952 7.808 17.976 ;
     RECT  7.292 20.64 7.808 22.44 ;
     RECT  7.513 23.568 7.808 24.744 ;
     RECT  6.757 25.728 7.808 25.752 ;
     RECT  7.693 26.928 7.808 27.192 ;
     RECT  7.808 2.148 7.912 27.552 ;
     RECT  7.912 2.418 8 27.552 ;
     RECT  8 2.418 8.104 27.822 ;
     RECT  8.104 20.64 8.813 25.752 ;
     RECT  8.104 13.68 8.957 13.704 ;
     RECT  8.104 26.976 9.313 27.192 ;
     RECT  8.813 23.136 9.529 25.752 ;
     RECT  9.313 26.784 9.529 27.192 ;
     RECT  9.133 14.736 9.673 14.76 ;
     RECT  8.813 20.64 9.74 21.816 ;
     RECT  9.673 14.256 10.508 14.76 ;
     RECT  8.104 17.952 10.508 17.976 ;
     RECT  9.74 19.92 10.508 21.816 ;
     RECT  9.529 23.136 10.508 27.192 ;
     RECT  10.508 2.148 10.612 27.552 ;
     RECT  10.612 2.418 10.7 27.552 ;
     RECT  10.7 2.418 10.804 27.822 ;
     RECT  10.804 19.632 10.829 21.816 ;
     RECT  10.804 14.736 10.973 15.816 ;
     RECT  10.804 23.136 11.045 27.336 ;
     RECT  11.045 23.136 11.171 25.752 ;
     RECT  10.973 15.024 11.909 15.816 ;
     RECT  10.829 20.64 11.977 21.816 ;
     RECT  11.171 23.136 11.977 23.976 ;
     RECT  11.045 27.312 12.125 27.336 ;
     RECT  11.909 15.792 12.373 15.816 ;
     RECT  11.171 25.248 12.409 25.752 ;
     RECT  10.829 19.632 12.709 19.656 ;
     RECT  12.409 25.248 12.769 26.232 ;
     RECT  12.709 19.248 12.956 19.656 ;
     RECT  11.977 20.64 12.956 23.976 ;
     RECT  10.804 17.952 13.093 17.976 ;
     RECT  12.949 12.528 13.165 12.552 ;
     RECT  10.804 13.632 13.165 13.656 ;
     RECT  13.165 12.528 13.208 13.656 ;
     RECT  12.373 15.792 13.208 16.392 ;
     RECT  13.093 17.952 13.208 18.216 ;
     RECT  12.956 19.248 13.208 23.976 ;
     RECT  12.769 25.008 13.208 26.232 ;
     RECT  13.208 2.148 13.312 27.552 ;
     RECT  13.312 2.418 13.4 27.552 ;
     RECT  13.4 2.418 13.504 27.822 ;
     RECT  13.504 19.248 13.745 25.56 ;
     RECT  13.504 11.376 13.817 14.52 ;
     RECT  13.504 15.792 13.889 16.392 ;
     RECT  13.745 19.248 14.429 25.512 ;
     RECT  13.817 12.24 14.785 13.176 ;
     RECT  13.817 14.496 14.785 14.52 ;
     RECT  13.504 17.472 14.821 17.976 ;
     RECT  13.889 15.792 15.289 15.816 ;
     RECT  14.821 17.424 15.289 17.976 ;
     RECT  14.429 20.64 15.325 25.512 ;
     RECT  14.785 12.24 15.349 14.52 ;
     RECT  15.445 10.992 15.469 11.016 ;
     RECT  15.469 10.704 15.908 11.016 ;
     RECT  15.349 12.24 15.908 14.664 ;
     RECT  15.289 15.792 15.908 17.976 ;
     RECT  14.429 19.248 15.908 19.368 ;
     RECT  15.325 20.64 15.908 26.232 ;
     RECT  15.908 2.148 16.012 27.552 ;
     RECT  16.012 2.418 16.1 27.552 ;
     RECT  16.1 2.418 16.204 27.822 ;
     RECT  16.369 30.048 16.441 30.072 ;
     RECT  16.204 14.496 16.481 19.32 ;
     RECT  16.204 10.704 16.595 10.728 ;
     RECT  16.481 14.64 16.697 19.32 ;
     RECT  16.645 27.936 16.741 28.008 ;
     RECT  16.441 30.048 16.837 30.12 ;
     RECT  16.697 16.992 16.841 19.32 ;
     RECT  16.697 14.64 16.877 15.816 ;
     RECT  16.837 29.664 16.979 30.12 ;
     RECT  16.741 27.936 17.125 28.104 ;
     RECT  16.204 12.48 17.237 13.128 ;
     RECT  16.979 30.048 17.309 30.12 ;
     RECT  17.237 13.104 17.381 13.128 ;
     RECT  17.125 27.936 17.413 28.488 ;
     RECT  17.309 30.048 17.417 30.072 ;
     RECT  16.877 15.792 17.555 15.816 ;
     RECT  17.413 27.936 17.669 29.064 ;
     RECT  17.669 27.936 17.701 28.488 ;
     RECT  17.701 27.888 17.893 28.488 ;
     RECT  16.841 16.992 18.037 18.744 ;
     RECT  17.341 11.952 18.608 11.976 ;
     RECT  17.509 14.208 18.608 14.232 ;
     RECT  18.037 16.992 18.608 19.512 ;
     RECT  16.204 20.64 18.608 26.568 ;
     RECT  17.893 27.84 18.608 28.488 ;
     RECT  18.608 2.148 18.712 28.488 ;
     RECT  18.712 2.418 18.904 28.488 ;
     RECT  18.904 27.312 19.217 28.488 ;
     RECT  19.217 27.312 19.433 28.44 ;
     RECT  18.904 16.176 19.469 18.744 ;
     RECT  18.904 20.16 19.721 26.232 ;
     RECT  19.469 16.176 19.897 16.776 ;
     RECT  19.721 20.16 19.933 26.04 ;
     RECT  19.469 17.952 20.437 18.744 ;
     RECT  19.933 20.064 20.437 26.04 ;
     RECT  18.904 10.848 20.509 10.872 ;
     RECT  20.437 14.832 20.533 14.856 ;
     RECT  19.897 16.032 20.533 16.776 ;
     RECT  19.433 27.312 21.089 28.104 ;
     RECT  20.533 14.832 21.157 16.776 ;
     RECT  20.437 17.952 21.157 26.04 ;
     RECT  21.089 27.312 21.157 27.912 ;
     RECT  21.157 14.832 21.197 27.912 ;
     RECT  18.904 13.008 21.301 13.032 ;
     RECT  20.509 10.848 21.308 11.256 ;
     RECT  21.301 12.336 21.308 13.032 ;
     RECT  21.197 14.832 21.308 27.822 ;
     RECT  21.308 2.148 21.412 27.822 ;
     RECT  21.412 2.418 21.604 27.822 ;
     RECT  21.604 17.952 22.205 26.52 ;
     RECT  22.205 17.952 22.277 19.368 ;
     RECT  22.277 17.952 22.313 18.744 ;
     RECT  21.604 12.336 22.741 12.36 ;
     RECT  21.604 13.68 22.741 13.704 ;
     RECT  21.604 11.232 22.745 11.256 ;
     RECT  22.741 12.336 22.777 13.704 ;
     RECT  22.777 11.952 22.781 14.472 ;
     RECT  22.205 20.64 22.849 26.52 ;
     RECT  22.781 13.104 22.931 14.472 ;
     RECT  22.849 20.64 22.981 26.664 ;
     RECT  22.313 17.952 23.173 18.504 ;
     RECT  21.604 9.648 23.245 10.2 ;
     RECT  22.981 20.64 23.857 26.904 ;
     RECT  23.857 20.16 24.001 26.904 ;
     RECT  23.245 9.552 24.008 10.2 ;
     RECT  22.781 11.952 24.008 12.072 ;
     RECT  22.931 13.68 24.008 14.472 ;
     RECT  21.604 15.696 24.008 15.72 ;
     RECT  23.173 17.088 24.008 18.504 ;
     RECT  24.001 20.064 24.008 26.904 ;
     RECT  24.008 2.148 24.073 27.552 ;
     RECT  24.073 2.148 24.112 27.624 ;
     RECT  24.112 2.418 24.2 27.624 ;
     RECT  24.2 2.418 24.304 27.822 ;
     RECT  24.304 20.064 24.419 27.384 ;
     RECT  24.304 9.552 24.46 10.296 ;
     RECT  24.304 13.872 24.545 18.984 ;
     RECT  24.46 9.552 24.581 10.248 ;
     RECT  24.545 17.424 25.049 18.984 ;
     RECT  24.581 10.08 25.069 10.248 ;
     RECT  24.545 13.872 25.265 16.2 ;
     RECT  24.304 11.952 25.436 12.36 ;
     RECT  25.436 11.28 25.513 12.36 ;
     RECT  25.069 10.128 25.523 10.248 ;
     RECT  25.513 11.28 26.197 12.744 ;
     RECT  25.265 13.92 26.389 16.2 ;
     RECT  26.389 13.92 26.449 16.296 ;
     RECT  25.049 17.472 26.449 18.984 ;
     RECT  26.449 13.92 26.557 18.984 ;
     RECT  26.197 10.896 26.593 12.744 ;
     RECT  26.557 13.92 26.593 19.032 ;
     RECT  26.053 9.792 26.708 9.816 ;
     RECT  26.593 10.896 26.708 19.032 ;
     RECT  24.419 20.16 26.708 27.384 ;
     RECT  26.708 2.148 26.812 27.552 ;
     RECT  26.812 2.418 26.9 27.552 ;
     RECT  26.9 2.418 27.004 27.822 ;
     RECT  27.004 9.792 27.425 11.976 ;
     RECT  27.425 9.792 27.605 11.88 ;
     RECT  27.004 13.392 27.785 18.84 ;
     RECT  27.785 13.392 27.875 18.792 ;
     RECT  27.004 8.256 28.073 8.28 ;
     RECT  27.004 19.92 28.325 27.192 ;
     RECT  28.325 20.352 28.501 27.192 ;
     RECT  28.393 11.904 28.609 11.928 ;
     RECT  27.605 9.792 28.753 10.92 ;
     RECT  28.609 11.904 28.753 12.552 ;
     RECT  27.875 13.536 28.933 13.848 ;
     RECT  27.875 14.88 28.933 18.792 ;
     RECT  28.933 13.536 28.969 18.792 ;
     RECT  28.753 9.792 29.005 12.552 ;
     RECT  28.969 13.536 29.005 19.272 ;
     RECT  29.005 9.792 29.185 19.272 ;
     RECT  29.185 9.6 29.408 19.272 ;
     RECT  28.501 20.352 29.408 27.384 ;
     RECT  29.408 2.148 29.512 27.552 ;
     RECT  29.512 2.418 29.6 27.552 ;
     RECT  29.6 2.418 29.704 27.822 ;
     RECT  29.704 16.896 30.053 27.192 ;
     RECT  30.053 16.896 30.233 19.56 ;
     RECT  29.704 9.36 30.269 11.976 ;
     RECT  29.704 13.008 30.269 15.816 ;
     RECT  30.053 20.64 30.275 27.192 ;
     RECT  30.269 13.008 30.629 13.032 ;
     RECT  30.269 10.704 30.773 11.976 ;
     RECT  30.275 20.64 30.853 26.904 ;
     RECT  30.773 10.848 30.953 11.976 ;
     RECT  30.269 9.36 31.021 9.384 ;
     RECT  31.021 9.072 31.061 9.384 ;
     RECT  30.269 14.112 31.273 15.816 ;
     RECT  30.953 10.848 31.741 11.736 ;
     RECT  31.273 13.824 31.777 15.816 ;
     RECT  30.853 20.64 31.957 26.568 ;
     RECT  31.061 9.072 32.108 9.096 ;
     RECT  31.741 10.176 32.108 11.736 ;
     RECT  31.777 13.632 32.108 15.816 ;
     RECT  30.233 17.088 32.108 19.56 ;
     RECT  31.957 20.64 32.108 27.096 ;
     RECT  32.108 2.148 32.212 27.552 ;
     RECT  32.212 2.418 32.3 27.552 ;
     RECT  32.3 2.418 32.404 27.822 ;
     RECT  32.404 13.008 32.465 27.096 ;
     RECT  32.465 17.472 32.573 27.096 ;
     RECT  32.573 19.92 33.578 27.096 ;
     RECT  33.578 26.784 33.689 27.096 ;
     RECT  32.404 9.792 33.937 11.736 ;
     RECT  32.465 13.008 33.937 16.344 ;
     RECT  33.937 9.792 34.225 16.344 ;
     RECT  34.225 9.6 34.621 16.344 ;
     RECT  32.573 17.472 34.621 18.84 ;
     RECT  34.621 9.6 34.808 18.84 ;
     RECT  33.578 19.92 34.808 25.8 ;
     RECT  33.689 26.784 34.808 26.808 ;
     RECT  34.808 2.148 34.912 27.552 ;
     RECT  34.912 2.418 35 27.552 ;
     RECT  35 2.418 35.104 27.822 ;
     RECT  35.104 13.68 35.165 14.424 ;
     RECT  35.104 9.6 35.489 12.552 ;
     RECT  35.104 26.832 35.669 27.096 ;
     RECT  35.669 26.832 35.705 26.856 ;
     RECT  35.489 12.48 36.029 12.552 ;
     RECT  35.489 9.6 36.065 11.4 ;
     RECT  36.065 10.032 36.101 11.4 ;
     RECT  35.165 13.68 36.101 14.232 ;
     RECT  35.104 15.456 36.317 25.512 ;
     RECT  36.101 13.92 36.425 14.232 ;
     RECT  36.425 14.112 36.781 14.232 ;
     RECT  36.317 15.456 36.781 18.984 ;
     RECT  36.101 10.704 37.069 11.4 ;
     RECT  36.029 12.528 37.177 12.552 ;
     RECT  36.317 20.064 37.213 25.512 ;
     RECT  37.213 20.064 37.465 25.848 ;
     RECT  37.069 10.704 37.508 11.448 ;
     RECT  37.177 12.528 37.508 12.6 ;
     RECT  36.781 14.112 37.508 18.984 ;
     RECT  37.465 20.064 37.508 26.376 ;
     RECT  37.508 2.148 37.612 27.552 ;
     RECT  37.612 2.418 37.7 27.552 ;
     RECT  37.7 2.418 37.804 27.822 ;
     RECT  37.804 10.704 37.937 27.624 ;
     RECT  37.937 17.088 38.045 27.624 ;
     RECT  38.045 17.376 38.261 27.624 ;
     RECT  37.937 10.704 38.579 15.816 ;
     RECT  38.261 17.424 38.771 27.624 ;
     RECT  38.771 20.592 38.837 27.624 ;
     RECT  38.771 17.424 39.229 19.272 ;
     RECT  38.579 10.944 39.625 15.816 ;
     RECT  39.229 17.232 39.625 19.272 ;
     RECT  38.837 20.592 39.841 27.096 ;
     RECT  39.884 30.144 39.971 30.168 ;
     RECT  39.841 20.304 40.201 27.432 ;
     RECT  39.625 10.944 40.208 19.272 ;
     RECT  40.201 20.304 40.208 27.624 ;
     RECT  40.208 2.148 40.312 27.624 ;
     RECT  40.312 2.418 40.4 27.624 ;
     RECT  40.4 2.418 40.504 27.822 ;
     RECT  40.504 10.944 40.673 13.656 ;
     RECT  40.673 10.944 40.787 12.552 ;
     RECT  40.504 15.12 41.069 27.624 ;
     RECT  41.069 15.12 41.105 27.432 ;
     RECT  40.787 10.944 41.213 11.544 ;
     RECT  41.105 15.12 41.411 26.952 ;
     RECT  41.411 20.304 41.789 26.952 ;
     RECT  41.411 15.12 41.861 19.272 ;
     RECT  40.787 12.528 42.469 12.552 ;
     RECT  41.861 15.12 42.469 16.104 ;
     RECT  41.213 10.944 42.685 10.968 ;
     RECT  42.469 11.952 42.757 12.552 ;
     RECT  40.673 13.632 42.757 13.656 ;
     RECT  42.685 10.704 42.793 10.968 ;
     RECT  42.757 11.952 42.793 13.656 ;
     RECT  42.793 10.704 42.908 13.656 ;
     RECT  42.469 14.784 42.908 16.104 ;
     RECT  41.861 17.136 42.908 19.272 ;
     RECT  41.789 20.304 42.908 26.856 ;
     RECT  42.908 2.148 43.012 27.552 ;
     RECT  43.012 2.418 43.1 27.552 ;
     RECT  43.1 2.418 43.204 27.822 ;
     RECT  43.204 10.944 43.265 12.6 ;
     RECT  43.204 20.544 43.331 26.904 ;
     RECT  43.189 30.144 43.337 30.168 ;
     RECT  43.331 20.592 44.233 26.904 ;
     RECT  43.204 13.584 44.345 14.232 ;
     RECT  43.204 15.792 44.413 19.272 ;
     RECT  44.233 20.592 44.413 27.144 ;
     RECT  44.413 14.976 44.483 27.144 ;
     RECT  43.265 11.424 44.701 12.6 ;
     RECT  44.345 13.584 44.701 13.608 ;
     RECT  44.485 30.144 44.921 30.168 ;
     RECT  44.483 17.136 44.953 27.144 ;
     RECT  44.483 14.976 45.493 15.816 ;
     RECT  44.701 11.424 45.608 13.608 ;
     RECT  45.493 14.64 45.608 15.816 ;
     RECT  44.953 17.136 45.608 27.384 ;
     RECT  45.608 2.148 45.712 27.552 ;
     RECT  45.712 2.418 45.8 27.552 ;
     RECT  45.8 2.418 45.904 27.822 ;
     RECT  45.904 11.376 46.019 13.608 ;
     RECT  45.904 14.64 46.325 27.384 ;
     RECT  46.019 11.424 46.577 13.608 ;
     RECT  46.325 14.784 46.577 27.384 ;
     RECT  46.577 11.424 46.972 12.216 ;
     RECT  45.904 8.496 47.041 8.52 ;
     RECT  46.577 14.784 47.045 27.048 ;
     RECT  47.045 14.784 47.068 26.808 ;
     RECT  46.972 11.424 47.153 11.448 ;
     RECT  46.577 13.584 47.221 13.608 ;
     RECT  47.221 13.584 47.222 13.656 ;
     RECT  47.068 14.784 47.261 26.328 ;
     RECT  47.222 13.632 47.977 13.656 ;
     RECT  47.261 17.136 48.157 26.328 ;
     RECT  47.261 14.784 48.193 16.008 ;
     RECT  47.041 8.496 48.308 8.808 ;
     RECT  48.181 11.232 48.308 11.256 ;
     RECT  47.977 13.632 48.308 13.704 ;
     RECT  48.193 14.736 48.308 16.008 ;
     RECT  48.157 17.136 48.308 26.568 ;
     RECT  48.308 2.148 48.412 27.552 ;
     RECT  48.412 2.418 48.5 27.552 ;
     RECT  48.5 2.418 48.604 27.822 ;
     RECT  48.604 13.632 48.701 16.008 ;
     RECT  48.701 13.632 49.349 15.96 ;
     RECT  48.604 17.376 49.813 26.952 ;
     RECT  49.349 13.728 49.997 15.96 ;
     RECT  49.813 17.328 50.209 26.952 ;
     RECT  48.604 8.496 50.245 8.808 ;
     RECT  48.604 9.888 50.245 9.912 ;
     RECT  49.997 14.4 50.677 15.96 ;
     RECT  50.209 16.944 50.677 26.952 ;
     RECT  50.245 8.496 51.008 9.912 ;
     RECT  48.604 11.232 51.008 11.256 ;
     RECT  50.677 14.4 51.008 27.096 ;
     RECT  51.008 2.148 51.112 27.552 ;
     RECT  51.112 2.418 51.2 27.552 ;
     RECT  51.2 2.418 51.304 27.822 ;
     RECT  51.304 17.376 52.405 27.096 ;
     RECT  52.405 17.232 52.549 27.096 ;
     RECT  51.304 8.496 52.765 9.912 ;
     RECT  51.304 15.792 52.94 15.816 ;
     RECT  52.549 17.136 52.94 27.096 ;
     RECT  52.765 8.496 53.269 10.104 ;
     RECT  53.269 8.496 53.708 10.2 ;
     RECT  51.304 11.232 53.708 11.256 ;
     RECT  52.94 15.792 53.708 27.096 ;
     RECT  53.708 2.148 53.812 27.552 ;
     RECT  53.812 2.418 53.9 27.552 ;
     RECT  53.9 2.418 54.004 27.822 ;
     RECT  54.004 17.136 54.209 27.192 ;
     RECT  54.209 17.376 54.245 27.192 ;
     RECT  54.245 17.472 54.281 27.192 ;
     RECT  54.004 8.496 54.857 10.2 ;
     RECT  54.857 8.496 56.077 10.152 ;
     RECT  54.004 11.376 56.077 11.4 ;
     RECT  56.077 8.496 56.293 11.4 ;
     RECT  56.293 8.496 56.408 11.448 ;
     RECT  54.004 15.792 56.408 15.816 ;
     RECT  54.281 17.472 56.408 27.048 ;
     RECT  56.408 2.148 56.512 27.552 ;
     RECT  56.512 2.418 56.6 27.552 ;
     RECT  56.6 2.418 56.704 27.822 ;
     RECT  56.704 17.472 57.841 26.856 ;
     RECT  57.841 17.472 58.345 27.144 ;
     RECT  56.704 8.496 58.705 11.016 ;
     RECT  58.705 8.496 59.108 11.16 ;
     RECT  56.704 15.792 59.108 15.816 ;
     RECT  58.345 17.472 59.108 27.192 ;
     RECT  59.108 2.148 59.212 27.552 ;
     RECT  59.212 2.418 59.3 27.552 ;
     RECT  59.3 2.418 59.404 27.822 ;
     RECT  59.404 17.472 59.555 27.192 ;
     RECT  59.404 15.408 59.753 15.816 ;
     RECT  59.555 17.472 59.843 25.848 ;
     RECT  59.555 27.168 60.005 27.192 ;
     RECT  59.843 19.824 60.221 25.848 ;
     RECT  59.404 13.536 60.949 13.56 ;
     RECT  60.221 19.824 61.189 25.8 ;
     RECT  59.843 17.472 61.429 18.744 ;
     RECT  59.404 8.496 61.513 12.504 ;
     RECT  60.949 13.536 61.513 13.608 ;
     RECT  61.513 8.496 61.541 13.608 ;
     RECT  61.429 17.136 61.573 18.744 ;
     RECT  61.189 19.824 61.573 25.848 ;
     RECT  61.541 8.352 61.58 13.608 ;
     RECT  59.753 15.408 61.58 15.432 ;
     RECT  61.573 7.344 61.621 7.368 ;
     RECT  61.58 8.352 61.621 15.432 ;
     RECT  61.621 7.344 61.808 15.432 ;
     RECT  61.573 17.136 61.808 25.848 ;
     RECT  61.808 2.148 61.912 27.552 ;
     RECT  61.912 2.418 62 27.552 ;
     RECT  62 2.418 62.104 27.822 ;
     RECT  62.104 17.088 62.201 18.744 ;
     RECT  62.201 17.088 62.237 18.216 ;
     RECT  62.237 17.088 62.273 17.736 ;
     RECT  62.104 6.24 62.317 14.28 ;
     RECT  62.317 14.256 62.435 14.28 ;
     RECT  62.317 6.24 62.627 12.936 ;
     RECT  62.273 17.088 62.633 17.448 ;
     RECT  62.633 17.088 62.669 17.112 ;
     RECT  62.627 6.768 62.723 12.936 ;
     RECT  62.104 19.92 62.723 26.808 ;
     RECT  62.723 19.92 62.764 26.712 ;
     RECT  62.723 6.864 63.349 12.936 ;
     RECT  63.349 6.864 64.692 6.888 ;
     RECT  63.349 6.888 64.716 6.96 ;
     RECT  63.349 6.96 64.692 6.984 ;
     RECT  63.349 6.984 64.716 7.056 ;
     RECT  63.349 7.056 64.692 7.08 ;
     RECT  63.349 7.08 64.716 7.152 ;
     RECT  63.349 7.152 64.692 7.176 ;
     RECT  63.349 7.176 64.716 7.248 ;
     RECT  63.349 7.248 64.692 7.272 ;
     RECT  63.349 7.272 64.716 7.344 ;
     RECT  63.349 7.344 64.692 7.368 ;
     RECT  63.349 7.368 64.716 7.44 ;
     RECT  63.349 7.44 64.692 7.464 ;
     RECT  63.349 7.464 64.716 7.536 ;
     RECT  63.349 7.536 64.692 7.56 ;
     RECT  63.349 7.56 64.716 7.632 ;
     RECT  63.349 7.632 64.692 7.656 ;
     RECT  63.349 7.656 64.716 7.728 ;
     RECT  63.349 7.728 64.692 7.752 ;
     RECT  63.349 7.752 64.716 7.824 ;
     RECT  63.349 7.824 64.692 7.848 ;
     RECT  63.349 7.848 64.716 7.92 ;
     RECT  63.349 7.92 64.692 7.944 ;
     RECT  63.349 7.944 64.716 8.016 ;
     RECT  63.349 8.016 64.692 8.04 ;
     RECT  63.349 8.04 64.716 8.112 ;
     RECT  63.349 8.112 64.692 8.136 ;
     RECT  63.349 8.136 64.716 8.208 ;
     RECT  63.349 8.208 64.692 8.232 ;
     RECT  63.349 8.232 64.716 8.304 ;
     RECT  63.349 8.304 64.692 8.328 ;
     RECT  63.349 8.328 64.716 8.4 ;
     RECT  63.349 8.4 64.692 8.424 ;
     RECT  63.349 8.424 64.716 8.496 ;
     RECT  63.349 8.496 64.692 8.52 ;
     RECT  63.349 8.52 64.716 8.592 ;
     RECT  63.349 8.592 64.692 8.616 ;
     RECT  63.349 8.616 64.716 8.688 ;
     RECT  63.349 8.688 64.692 8.712 ;
     RECT  63.349 8.712 64.716 8.784 ;
     RECT  63.349 8.784 64.692 8.808 ;
     RECT  63.349 8.808 64.716 8.88 ;
     RECT  63.349 8.88 64.692 8.904 ;
     RECT  63.349 8.904 64.716 8.976 ;
     RECT  63.349 8.976 64.692 9 ;
     RECT  63.349 9 64.716 9.072 ;
     RECT  63.349 9.072 64.692 9.096 ;
     RECT  63.349 9.096 64.716 9.168 ;
     RECT  63.349 9.168 64.692 9.192 ;
     RECT  63.349 9.192 64.716 9.264 ;
     RECT  63.349 9.264 64.692 9.288 ;
     RECT  63.349 9.288 64.716 9.36 ;
     RECT  63.349 9.36 64.692 9.384 ;
     RECT  63.349 9.384 64.716 9.456 ;
     RECT  63.349 9.456 64.692 9.48 ;
     RECT  63.349 9.48 64.716 9.552 ;
     RECT  63.349 9.552 64.692 9.576 ;
     RECT  63.349 9.576 64.716 9.648 ;
     RECT  63.349 9.648 64.692 9.672 ;
     RECT  63.349 9.672 64.716 9.744 ;
     RECT  63.349 9.744 64.692 9.768 ;
     RECT  63.349 9.768 64.716 9.84 ;
     RECT  63.349 9.84 64.692 9.864 ;
     RECT  63.349 9.864 64.716 9.936 ;
     RECT  63.349 9.936 64.692 9.96 ;
     RECT  63.349 9.96 64.716 10.032 ;
     RECT  63.349 10.032 64.692 10.056 ;
     RECT  63.349 10.056 64.716 10.128 ;
     RECT  63.349 10.128 64.692 10.152 ;
     RECT  63.349 10.152 64.716 10.224 ;
     RECT  63.349 10.224 64.692 10.248 ;
     RECT  63.349 10.248 64.716 10.32 ;
     RECT  63.349 10.32 64.692 10.344 ;
     RECT  63.349 10.344 64.716 10.416 ;
     RECT  63.349 10.416 64.692 10.44 ;
     RECT  63.349 10.44 64.716 10.512 ;
     RECT  63.349 10.512 64.692 10.536 ;
     RECT  63.349 10.536 64.716 10.608 ;
     RECT  63.349 10.608 64.692 10.632 ;
     RECT  63.349 10.632 64.716 10.704 ;
     RECT  63.349 10.704 64.692 10.728 ;
     RECT  63.349 10.728 64.716 10.8 ;
     RECT  63.349 10.8 64.692 10.824 ;
     RECT  63.349 10.824 64.716 10.896 ;
     RECT  63.349 10.896 64.692 10.92 ;
     RECT  63.349 10.92 64.716 10.992 ;
     RECT  63.349 10.992 64.692 11.016 ;
     RECT  63.349 11.016 64.716 11.088 ;
     RECT  63.349 11.088 64.692 11.112 ;
     RECT  63.349 11.112 64.716 11.184 ;
     RECT  63.349 11.184 64.692 11.208 ;
     RECT  63.349 11.208 64.716 11.28 ;
     RECT  63.349 11.28 64.692 11.304 ;
     RECT  63.349 11.304 64.716 11.376 ;
     RECT  63.349 11.376 64.692 11.4 ;
     RECT  63.349 11.4 64.716 11.472 ;
     RECT  63.349 11.472 64.692 11.496 ;
     RECT  63.349 11.496 64.716 11.568 ;
     RECT  63.349 11.568 64.692 11.592 ;
     RECT  63.349 11.592 64.716 11.664 ;
     RECT  63.349 11.664 64.692 11.688 ;
     RECT  63.349 11.688 64.716 11.76 ;
     RECT  63.349 11.76 64.692 11.784 ;
     RECT  63.349 11.784 64.716 11.856 ;
     RECT  63.349 11.856 64.692 11.88 ;
     RECT  63.349 11.88 64.716 11.952 ;
     RECT  63.349 11.952 64.692 11.976 ;
     RECT  63.349 11.976 64.716 12.048 ;
     RECT  63.349 12.048 64.692 12.072 ;
     RECT  63.349 12.072 64.716 12.144 ;
     RECT  63.349 12.144 64.692 12.168 ;
     RECT  63.349 12.168 64.716 12.24 ;
     RECT  63.349 12.24 64.692 12.264 ;
     RECT  63.349 12.264 64.716 12.336 ;
     RECT  63.349 12.336 64.692 12.36 ;
     RECT  63.349 12.36 64.716 12.432 ;
     RECT  63.349 12.432 64.692 12.456 ;
     RECT  63.349 12.456 64.716 12.528 ;
     RECT  63.349 12.528 64.692 12.552 ;
     RECT  63.349 12.552 64.716 12.624 ;
     RECT  63.349 12.624 64.692 12.648 ;
     RECT  63.349 12.648 64.716 12.72 ;
     RECT  63.349 12.72 64.692 12.744 ;
     RECT  63.349 12.744 64.716 12.816 ;
     RECT  63.349 12.816 64.692 12.84 ;
     RECT  63.349 12.84 64.716 12.912 ;
     RECT  63.349 12.912 64.692 12.936 ;
     RECT  63.349 12.936 64.716 13.008 ;
     RECT  63.349 13.008 64.692 13.032 ;
     RECT  62.764 19.92 64.692 19.944 ;
     RECT  62.764 19.944 64.716 20.016 ;
     RECT  62.764 20.016 64.692 20.04 ;
     RECT  62.764 20.04 64.716 20.112 ;
     RECT  62.764 20.112 64.692 20.136 ;
     RECT  62.764 20.136 64.716 20.208 ;
     RECT  62.764 20.208 64.692 20.232 ;
     RECT  62.764 20.232 64.716 20.304 ;
     RECT  62.764 20.304 64.692 20.328 ;
     RECT  62.764 20.328 64.716 20.4 ;
     RECT  62.764 20.4 64.692 20.424 ;
     RECT  62.764 20.424 64.716 20.496 ;
     RECT  62.764 20.496 64.692 20.52 ;
     RECT  62.764 20.52 64.716 20.592 ;
     RECT  62.764 20.592 64.692 20.616 ;
     RECT  62.764 20.616 64.716 20.688 ;
     RECT  62.764 20.688 64.692 20.712 ;
     RECT  62.764 20.712 64.716 20.784 ;
     RECT  62.764 20.784 64.692 20.808 ;
     RECT  62.764 20.808 64.716 20.88 ;
     RECT  62.764 20.88 64.692 20.904 ;
     RECT  62.764 20.904 64.716 20.976 ;
     RECT  62.764 20.976 64.692 21 ;
     RECT  62.764 21 64.716 21.072 ;
     RECT  62.764 21.072 64.692 21.096 ;
     RECT  62.764 21.096 64.716 21.168 ;
     RECT  62.764 21.168 64.692 21.192 ;
     RECT  62.764 21.192 64.716 21.264 ;
     RECT  62.764 21.264 64.692 21.288 ;
     RECT  62.764 21.288 64.716 21.36 ;
     RECT  62.764 21.36 64.692 21.384 ;
     RECT  62.764 21.384 64.716 21.456 ;
     RECT  62.764 21.456 64.692 21.48 ;
     RECT  62.764 21.48 64.716 21.552 ;
     RECT  62.764 21.552 64.692 21.576 ;
     RECT  62.764 21.576 64.716 21.648 ;
     RECT  62.764 21.648 64.692 21.672 ;
     RECT  62.764 21.672 64.716 21.744 ;
     RECT  62.764 21.744 64.692 21.768 ;
     RECT  62.764 21.768 64.716 21.84 ;
     RECT  62.764 21.84 64.692 21.864 ;
     RECT  62.764 21.864 64.716 21.936 ;
     RECT  62.764 21.936 64.692 21.96 ;
     RECT  62.764 21.96 64.716 22.032 ;
     RECT  62.764 22.032 64.692 22.056 ;
     RECT  62.764 22.056 64.716 22.128 ;
     RECT  62.764 22.128 64.692 22.152 ;
     RECT  62.764 22.152 64.716 22.224 ;
     RECT  62.764 22.224 64.692 22.248 ;
     RECT  62.764 22.248 64.716 22.32 ;
     RECT  62.764 22.32 64.692 22.344 ;
     RECT  62.764 22.344 64.716 22.416 ;
     RECT  62.764 22.416 64.692 22.44 ;
     RECT  62.764 22.44 64.716 22.512 ;
     RECT  62.764 22.512 64.692 22.536 ;
     RECT  62.764 22.536 64.716 22.608 ;
     RECT  62.764 22.608 64.692 22.632 ;
     RECT  62.764 22.632 64.716 22.704 ;
     RECT  62.764 22.704 64.692 22.728 ;
     RECT  62.764 22.728 64.716 22.8 ;
     RECT  62.764 22.8 64.692 22.824 ;
     RECT  62.764 22.824 64.716 22.896 ;
     RECT  62.764 22.896 64.692 22.92 ;
     RECT  62.764 22.92 64.716 22.992 ;
     RECT  62.764 22.992 64.692 23.016 ;
     RECT  62.764 23.016 64.716 23.088 ;
     RECT  62.764 23.088 64.692 23.112 ;
     RECT  62.764 23.112 64.716 23.184 ;
     RECT  62.764 23.184 64.692 23.208 ;
     RECT  62.764 23.208 64.716 23.28 ;
     RECT  62.764 23.28 64.692 23.304 ;
     RECT  62.764 23.304 64.716 23.376 ;
     RECT  62.764 23.376 64.692 23.4 ;
     RECT  62.764 23.4 64.716 23.472 ;
     RECT  62.764 23.472 64.692 23.496 ;
     RECT  62.764 23.496 64.716 23.568 ;
     RECT  62.764 23.568 64.692 23.592 ;
     RECT  62.764 23.592 64.716 23.664 ;
     RECT  62.764 23.664 64.692 23.688 ;
     RECT  62.764 23.688 64.716 23.76 ;
     RECT  62.764 23.76 64.692 23.784 ;
     RECT  62.764 23.784 64.716 23.856 ;
     RECT  62.764 23.856 64.692 23.88 ;
     RECT  62.764 23.88 64.716 23.952 ;
     RECT  62.764 23.952 64.692 23.976 ;
     RECT  62.764 23.976 64.716 24.048 ;
     RECT  62.764 24.048 64.692 24.072 ;
     RECT  62.764 24.072 64.716 24.144 ;
     RECT  62.764 24.144 64.692 24.168 ;
     RECT  62.764 24.168 64.716 24.24 ;
     RECT  62.764 24.24 64.692 24.264 ;
     RECT  62.764 24.264 64.716 24.336 ;
     RECT  62.764 24.336 64.692 24.36 ;
     RECT  62.764 24.36 64.716 24.432 ;
     RECT  62.764 24.432 64.692 24.456 ;
     RECT  62.764 24.456 64.716 24.528 ;
     RECT  62.764 24.528 64.692 24.552 ;
     RECT  62.764 24.552 64.716 24.624 ;
     RECT  62.764 24.624 64.692 24.648 ;
     RECT  62.764 24.648 64.716 24.72 ;
     RECT  62.764 24.72 64.692 24.744 ;
     RECT  62.764 24.744 64.716 24.816 ;
     RECT  62.764 24.816 64.692 24.84 ;
     RECT  62.764 24.84 64.716 24.912 ;
     RECT  62.764 24.912 64.692 24.936 ;
     RECT  62.764 24.936 64.716 25.008 ;
     RECT  62.764 25.008 64.692 25.032 ;
     RECT  62.764 25.032 64.716 25.104 ;
     RECT  62.764 25.104 64.692 25.128 ;
     RECT  62.764 25.128 64.716 25.2 ;
     RECT  62.764 25.2 64.692 25.224 ;
     RECT  62.764 25.224 64.716 25.296 ;
     RECT  62.764 25.296 64.692 25.32 ;
     RECT  62.764 25.32 64.716 25.392 ;
     RECT  62.764 25.392 64.692 25.416 ;
     RECT  62.764 25.416 64.716 25.488 ;
     RECT  62.764 25.488 64.692 25.512 ;
     RECT  62.764 25.512 64.716 25.584 ;
     RECT  62.764 25.584 64.692 25.608 ;
     RECT  62.764 25.608 64.716 25.68 ;
     RECT  62.764 25.68 64.692 25.704 ;
     RECT  62.764 25.704 64.716 25.776 ;
     RECT  62.764 25.776 64.692 25.8 ;
     RECT  62.764 25.8 64.716 25.872 ;
     RECT  62.764 25.872 64.692 25.896 ;
     RECT  62.764 25.896 64.716 25.968 ;
     RECT  62.764 25.968 64.692 25.992 ;
     RECT  64.716 9.216 64.757 9.264 ;
     RECT  64.716 9.288 64.757 9.36 ;
     RECT  64.716 9.384 64.757 9.456 ;
     RECT  64.716 9.48 64.757 9.552 ;
     RECT  64.716 9.576 64.757 9.648 ;
     RECT  64.716 9.672 64.757 9.744 ;
     RECT  64.716 9.768 64.757 9.816 ;
     RECT  64.716 21.504 64.757 21.528 ;
     RECT  64.716 22.848 64.757 22.872 ;
     RECT  64.716 24.768 64.757 24.792 ;
    LAYER M5 ;
     RECT  2.4 2.137 2.52 2.151 ;
     RECT  5.1 2.137 5.22 2.151 ;
     RECT  7.8 2.137 7.92 2.151 ;
     RECT  10.5 2.137 10.62 2.151 ;
     RECT  13.2 2.137 13.32 2.151 ;
     RECT  15.9 2.137 16.02 2.151 ;
     RECT  18.6 2.137 18.72 2.151 ;
     RECT  21.3 2.137 21.42 2.151 ;
     RECT  24 2.137 24.12 2.151 ;
     RECT  26.7 2.137 26.82 2.151 ;
     RECT  29.4 2.137 29.52 2.151 ;
     RECT  32.1 2.137 32.22 2.151 ;
     RECT  34.8 2.137 34.92 2.151 ;
     RECT  37.5 2.137 37.62 2.151 ;
     RECT  40.2 2.137 40.32 2.151 ;
     RECT  42.9 2.137 43.02 2.151 ;
     RECT  45.6 2.137 45.72 2.151 ;
     RECT  48.3 2.137 48.42 2.151 ;
     RECT  51 2.137 51.12 2.151 ;
     RECT  53.7 2.137 53.82 2.151 ;
     RECT  56.4 2.137 56.52 2.151 ;
     RECT  59.1 2.137 59.22 2.151 ;
     RECT  61.8 2.137 61.92 2.151 ;
     RECT  61.8 2.151 62.112 6.229 ;
     RECT  61.8 6.229 62.616 6.757 ;
     RECT  61.8 6.757 62.712 6.899 ;
     RECT  61.8 6.899 62.616 7.333 ;
     RECT  61.584 7.333 62.616 7.909 ;
     RECT  56.4 2.151 56.712 8.773 ;
     RECT  61.584 7.909 62.664 9.203 ;
     RECT  61.584 9.203 62.616 9.395 ;
     RECT  24 2.151 24.312 9.541 ;
     RECT  61.584 9.395 62.52 9.589 ;
     RECT  34.8 2.151 35.112 9.637 ;
     RECT  34.8 9.637 35.784 9.925 ;
     RECT  24 9.541 24.408 10.307 ;
     RECT  15.9 2.151 16.212 10.693 ;
     RECT  37.5 2.151 37.812 10.693 ;
     RECT  61.488 9.589 62.52 10.741 ;
     RECT  61.488 10.741 62.712 10.883 ;
     RECT  34.464 9.925 35.784 10.979 ;
     RECT  15.9 10.693 16.584 10.981 ;
     RECT  34.464 10.979 35.112 11.171 ;
     RECT  48.3 2.151 48.612 11.221 ;
     RECT  45.6 2.151 45.912 11.365 ;
     RECT  45.6 11.365 46.008 11.413 ;
     RECT  56.304 8.773 56.712 11.459 ;
     RECT  40.2 2.151 40.512 11.797 ;
     RECT  25.488 10.213 25.512 11.941 ;
     RECT  26.7 2.151 27.012 11.941 ;
     RECT  40.2 11.797 40.776 11.941 ;
     RECT  59.1 2.151 59.412 11.941 ;
     RECT  37.5 10.693 38.568 11.989 ;
     RECT  61.488 10.883 62.664 12.035 ;
     RECT  45.6 11.413 46.92 12.227 ;
     RECT  61.488 12.035 62.52 12.323 ;
     RECT  42.9 2.151 43.212 12.469 ;
     RECT  59.1 11.941 59.64 12.469 ;
     RECT  37.5 11.989 38.808 12.563 ;
     RECT  40.032 11.941 40.776 12.563 ;
     RECT  61.536 12.323 62.52 12.611 ;
     RECT  42.9 12.469 43.32 13.045 ;
     RECT  15.456 10.981 16.584 13.141 ;
     RECT  0.192 13.093 0.216 13.189 ;
     RECT  25.488 11.941 27.012 13.381 ;
     RECT  59.1 12.469 60.264 13.525 ;
     RECT  59.1 13.525 60.36 13.573 ;
     RECT  61.536 12.611 62.424 13.573 ;
     RECT  42.768 13.045 43.32 13.667 ;
     RECT  22.896 13.093 22.92 13.715 ;
     RECT  48.192 11.221 48.612 13.715 ;
     RECT  15.36 13.141 16.584 14.197 ;
     RECT  48.3 13.715 48.612 14.197 ;
     RECT  59.1 13.573 62.424 14.291 ;
     RECT  15.36 14.197 17.544 14.675 ;
     RECT  37.5 12.563 38.568 14.773 ;
     RECT  42.9 13.667 43.32 14.773 ;
     RECT  21.3 2.151 21.612 14.821 ;
     RECT  33.792 14.389 33.816 14.915 ;
     RECT  45.6 12.227 46.44 15.061 ;
     RECT  44.976 15.061 46.44 15.301 ;
     RECT  10.5 2.151 10.812 15.349 ;
     RECT  25.488 13.381 27.864 15.395 ;
     RECT  42.48 14.773 43.32 15.443 ;
     RECT  59.1 14.291 62.112 15.443 ;
     RECT  10.5 15.349 11.256 15.827 ;
     RECT  15.9 14.675 17.544 15.827 ;
     RECT  25.488 15.395 27.012 15.925 ;
     RECT  44.448 15.301 46.44 15.973 ;
     RECT  53.7 2.151 54.012 16.405 ;
     RECT  44.448 15.973 46.728 16.595 ;
     RECT  20.544 14.821 21.612 16.787 ;
     RECT  51 2.151 51.312 16.933 ;
     RECT  24 10.307 24.312 17.077 ;
     RECT  25.344 15.925 27.012 17.077 ;
     RECT  61.8 15.443 62.112 17.125 ;
     RECT  52.992 16.405 54.012 17.461 ;
     RECT  48.3 14.197 49.416 17.507 ;
     RECT  59.1 15.443 60.36 17.605 ;
     RECT  61.44 17.125 62.112 17.605 ;
     RECT  50.592 16.933 51.312 17.651 ;
     RECT  23.376 17.077 24.312 17.699 ;
     RECT  59.1 17.605 62.112 17.795 ;
     RECT  0.192 13.189 0.36 17.987 ;
     RECT  21.168 16.787 21.612 18.133 ;
     RECT  25.344 17.077 27.864 18.179 ;
     RECT  13.2 2.151 13.512 18.181 ;
     RECT  32.1 2.151 32.412 18.181 ;
     RECT  42.9 15.443 43.32 18.181 ;
     RECT  52.512 17.461 54.12 18.181 ;
     RECT  59.1 17.795 59.412 18.181 ;
     RECT  21.168 18.133 22.2 18.275 ;
     RECT  29.4 2.151 29.712 18.373 ;
     RECT  42.9 18.181 43.56 18.421 ;
     RECT  52.416 18.181 54.456 18.467 ;
     RECT  42.768 18.421 43.56 18.563 ;
     RECT  28.464 18.373 29.712 18.611 ;
     RECT  34.8 11.171 35.112 18.613 ;
     RECT  15.9 15.827 17.256 18.709 ;
     RECT  18.6 2.151 18.912 18.709 ;
     RECT  29.4 18.611 29.712 18.709 ;
     RECT  21.168 18.275 21.612 18.755 ;
     RECT  58.992 18.181 59.412 18.757 ;
     RECT  29.4 18.709 29.88 18.851 ;
     RECT  31.824 18.181 32.412 18.851 ;
     RECT  53.7 18.467 54.456 18.851 ;
     RECT  24 17.699 24.312 18.949 ;
     RECT  25.344 18.179 27.012 18.949 ;
     RECT  40.032 12.563 40.512 18.997 ;
     RECT  42.9 18.563 43.56 19.043 ;
     RECT  34.8 18.613 35.88 19.235 ;
     RECT  52.416 18.467 52.44 19.235 ;
     RECT  13.104 18.181 13.512 19.237 ;
     RECT  15.9 18.709 18.912 19.283 ;
     RECT  12.72 19.237 13.512 19.333 ;
     RECT  58.896 18.757 59.412 19.333 ;
     RECT  44.976 16.595 46.728 19.379 ;
     RECT  17.232 19.283 18.912 19.523 ;
     RECT  48.3 17.507 48.612 19.525 ;
     RECT  49.584 18.757 49.608 19.571 ;
     RECT  12.72 19.333 13.656 19.667 ;
     RECT  21.3 18.755 21.612 19.861 ;
     RECT  10.5 15.827 10.812 19.909 ;
     RECT  53.7 18.851 54.12 19.909 ;
     RECT  48 19.525 48.612 20.051 ;
     RECT  24 18.949 27.012 20.099 ;
     RECT  37.5 14.773 38.76 20.099 ;
     RECT  18.6 19.523 18.912 20.149 ;
     RECT  40.032 18.997 41.4 20.293 ;
     RECT  40.032 20.293 41.832 20.339 ;
     RECT  58.896 19.333 59.832 20.339 ;
     RECT  61.056 17.795 62.112 20.389 ;
     RECT  60.96 20.389 62.112 20.485 ;
     RECT  9.792 19.909 10.812 20.579 ;
     RECT  42.9 19.043 43.32 20.579 ;
     RECT  53.7 19.909 54.264 20.629 ;
     RECT  53.04 20.629 54.264 20.677 ;
     RECT  17.232 19.523 17.256 20.725 ;
     RECT  18.6 20.149 19.032 20.725 ;
     RECT  52.416 20.677 54.264 20.771 ;
     RECT  21.3 19.861 22.056 20.819 ;
     RECT  25.344 20.099 27.012 20.819 ;
     RECT  60.96 20.485 62.616 21.013 ;
     RECT  51 17.651 51.312 21.109 ;
     RECT  41.808 20.339 41.832 21.155 ;
     RECT  0.192 17.987 0.216 21.203 ;
     RECT  48.3 20.051 48.612 21.205 ;
     RECT  17.232 20.725 19.032 21.299 ;
     RECT  52.416 20.771 52.536 21.299 ;
     RECT  53.7 20.771 54.264 21.301 ;
     RECT  55.248 19.237 55.272 21.301 ;
     RECT  53.7 21.301 55.272 21.347 ;
     RECT  47.904 21.205 48.612 21.395 ;
     RECT  6.768 21.301 6.792 21.397 ;
     RECT  7.8 2.151 8.112 21.397 ;
     RECT  37.5 20.099 37.812 21.493 ;
     RECT  59.1 20.339 59.832 21.541 ;
     RECT  60.96 21.013 62.664 21.541 ;
     RECT  29.4 18.851 29.712 21.637 ;
     RECT  50.448 21.109 51.312 21.637 ;
     RECT  56.4 11.459 56.712 21.637 ;
     RECT  33.504 21.109 33.528 21.683 ;
     RECT  59.1 21.541 62.664 21.683 ;
     RECT  49.824 21.637 51.312 21.781 ;
     RECT  61.2 21.683 62.664 21.973 ;
     RECT  53.7 21.347 55.032 22.067 ;
     RECT  57.744 21.637 57.768 22.067 ;
     RECT  12.72 19.667 13.512 22.069 ;
     RECT  40.032 20.339 40.512 22.069 ;
     RECT  49.824 21.781 52.008 22.115 ;
     RECT  61.2 21.973 62.76 22.115 ;
     RECT  48.3 21.395 48.612 22.117 ;
     RECT  61.2 22.115 62.568 22.163 ;
     RECT  24 20.099 24.312 22.165 ;
     RECT  53.7 22.067 54.012 22.165 ;
     RECT  48.3 22.117 49.032 22.355 ;
     RECT  50.112 22.115 52.008 22.355 ;
     RECT  6.768 21.397 8.112 22.451 ;
     RECT  23.76 22.165 24.312 22.451 ;
     RECT  37.5 21.493 37.944 22.451 ;
     RECT  56.016 21.637 56.712 22.451 ;
     RECT  44.976 19.379 46.056 22.595 ;
     RECT  42.9 20.579 43.212 22.597 ;
     RECT  47.088 22.453 47.112 22.643 ;
     RECT  21.3 20.819 21.612 22.741 ;
     RECT  42.096 22.597 43.212 22.741 ;
     RECT  59.1 21.683 60.072 22.741 ;
     RECT  40.032 22.069 40.968 22.787 ;
     RECT  37.5 22.451 37.812 22.789 ;
     RECT  58.128 22.741 60.072 22.931 ;
     RECT  44.976 22.595 45.912 22.979 ;
     RECT  53.52 22.165 54.012 23.027 ;
     RECT  20.88 22.741 21.612 23.173 ;
     RECT  12.72 22.069 13.656 23.267 ;
     RECT  40.032 22.787 40.728 23.267 ;
     RECT  40.032 23.267 40.512 23.269 ;
     RECT  61.2 22.163 62.112 23.269 ;
     RECT  10.5 20.579 10.812 23.317 ;
     RECT  20.88 23.173 22.392 23.411 ;
     RECT  50.112 22.355 51.312 23.459 ;
     RECT  58.128 22.931 59.88 23.459 ;
     RECT  60.912 23.269 62.568 23.749 ;
     RECT  2.4 2.151 2.712 23.845 ;
     RECT  5.1 2.151 5.412 23.845 ;
     RECT  7.8 22.451 8.112 23.845 ;
     RECT  24 22.451 24.312 23.893 ;
     RECT  56.4 22.451 56.712 23.893 ;
     RECT  17.472 21.299 18.912 23.987 ;
     RECT  17.616 23.987 18.912 24.035 ;
     RECT  42.096 22.741 43.752 24.131 ;
     RECT  53.568 23.027 54.012 24.227 ;
     RECT  48.3 22.355 48.612 24.277 ;
     RECT  10.5 23.317 11.16 24.323 ;
     RECT  2.4 23.845 3.624 24.371 ;
     RECT  37.008 22.789 37.812 24.371 ;
     RECT  12.72 23.267 13.512 24.373 ;
     RECT  39.936 23.269 40.512 24.373 ;
     RECT  48.3 24.277 49.032 24.419 ;
     RECT  39.936 24.373 40.632 24.421 ;
     RECT  37.056 24.371 37.812 24.467 ;
     RECT  39.936 24.421 40.728 24.469 ;
     RECT  34.8 19.235 35.64 24.563 ;
     RECT  56.4 23.893 57.576 24.563 ;
     RECT  60.912 23.749 62.664 24.563 ;
     RECT  4.992 23.845 5.412 24.611 ;
     RECT  60.96 24.563 62.664 24.611 ;
     RECT  7.8 23.845 8.76 24.659 ;
     RECT  21.168 23.411 22.392 24.757 ;
     RECT  42.096 24.131 43.212 24.853 ;
     RECT  53.7 24.227 54.012 24.853 ;
     RECT  55.008 22.067 55.032 24.853 ;
     RECT  29.4 21.637 30.456 24.997 ;
     RECT  17.76 24.035 18.912 25.045 ;
     RECT  37.5 24.467 37.812 25.045 ;
     RECT  39.36 24.469 40.728 25.045 ;
     RECT  51 23.459 51.312 25.045 ;
     RECT  12.72 24.373 13.896 25.139 ;
     RECT  53.7 24.853 55.032 25.139 ;
     RECT  59.1 23.459 59.88 25.139 ;
     RECT  37.5 25.045 40.728 25.141 ;
     RECT  41.952 24.853 43.212 25.141 ;
     RECT  21.168 24.757 22.488 25.235 ;
     RECT  37.5 25.141 43.212 25.283 ;
     RECT  28.848 24.997 30.456 25.523 ;
     RECT  39.36 25.283 43.212 25.573 ;
     RECT  24 23.893 25.128 25.669 ;
     RECT  12.72 25.139 13.512 25.715 ;
     RECT  50.88 25.045 51.312 25.715 ;
     RECT  6.768 22.451 6.792 25.763 ;
     RECT  53.7 25.139 54.36 25.763 ;
     RECT  60.96 24.611 62.112 25.763 ;
     RECT  39.36 25.573 43.464 25.811 ;
     RECT  61.2 25.763 62.112 25.859 ;
     RECT  39.936 25.811 43.464 26.003 ;
     RECT  17.76 25.045 19.08 26.051 ;
     RECT  21.3 25.235 22.488 26.101 ;
     RECT  28.848 25.523 30.36 26.101 ;
     RECT  42.192 26.003 43.464 26.147 ;
     RECT  26.256 20.819 27.012 26.291 ;
     RECT  42.192 26.147 43.212 26.387 ;
     RECT  59.1 25.139 59.412 26.485 ;
     RECT  21.3 26.101 23.016 26.531 ;
     RECT  61.8 25.859 62.112 26.677 ;
     RECT  24 25.669 25.272 26.723 ;
     RECT  37.5 25.283 37.812 26.725 ;
     RECT  39.936 26.003 40.92 26.771 ;
     RECT  28.512 26.101 30.36 26.773 ;
     RECT  42.72 26.387 43.212 26.819 ;
     RECT  46.992 25.717 47.016 26.819 ;
     RECT  61.8 26.677 62.712 26.819 ;
     RECT  22.992 26.531 23.016 26.915 ;
     RECT  28.512 26.773 30.84 26.915 ;
     RECT  28.512 26.915 30.264 27.203 ;
     RECT  59.1 26.485 59.544 27.203 ;
     RECT  18.6 26.051 19.08 27.301 ;
     RECT  24 26.723 25.176 27.395 ;
     RECT  26.4 26.291 27.012 27.395 ;
     RECT  28.512 27.203 29.712 27.395 ;
     RECT  37.5 26.725 38.76 27.635 ;
     RECT  21.3 26.531 21.612 27.781 ;
     RECT  2.4 24.371 2.712 27.819 ;
     RECT  5.1 24.611 5.412 27.819 ;
     RECT  7.8 24.659 8.112 27.819 ;
     RECT  10.5 24.323 10.812 27.819 ;
     RECT  13.2 25.715 13.512 27.819 ;
     RECT  15.9 19.283 16.212 27.819 ;
     RECT  24 27.395 24.312 27.819 ;
     RECT  26.7 27.395 27.012 27.819 ;
     RECT  29.4 27.395 29.712 27.819 ;
     RECT  32.1 18.851 32.412 27.819 ;
     RECT  34.8 24.563 35.112 27.819 ;
     RECT  37.5 27.635 37.812 27.819 ;
     RECT  42.9 26.819 43.212 27.819 ;
     RECT  45.6 22.979 45.912 27.819 ;
     RECT  48.3 24.419 48.612 27.819 ;
     RECT  51 25.715 51.312 27.819 ;
     RECT  53.7 25.763 54.012 27.819 ;
     RECT  56.4 24.563 56.712 27.819 ;
     RECT  59.1 27.203 59.412 27.819 ;
     RECT  61.8 26.819 62.112 27.819 ;
     RECT  18.6 27.301 19.464 27.829 ;
     RECT  2.592 27.819 2.712 27.833 ;
     RECT  5.292 27.819 5.412 27.833 ;
     RECT  7.992 27.819 8.112 27.833 ;
     RECT  10.692 27.819 10.812 27.833 ;
     RECT  13.392 27.819 13.512 27.833 ;
     RECT  16.092 27.819 16.212 27.833 ;
     RECT  20.976 27.781 21.612 27.833 ;
     RECT  24.192 27.819 24.312 27.833 ;
     RECT  26.892 27.819 27.012 27.833 ;
     RECT  29.592 27.819 29.712 27.833 ;
     RECT  32.292 27.819 32.412 27.833 ;
     RECT  34.992 27.819 35.112 27.833 ;
     RECT  37.692 27.819 37.812 27.833 ;
     RECT  39.936 26.771 40.512 27.833 ;
     RECT  43.092 27.819 43.212 27.833 ;
     RECT  45.792 27.819 45.912 27.833 ;
     RECT  48.492 27.819 48.612 27.833 ;
     RECT  51.192 27.819 51.312 27.833 ;
     RECT  53.892 27.819 54.012 27.833 ;
     RECT  56.592 27.819 56.712 27.833 ;
     RECT  59.292 27.819 59.412 27.833 ;
     RECT  61.992 27.819 62.112 27.833 ;
     RECT  17.904 27.829 19.464 27.877 ;
     RECT  20.976 27.833 21 27.923 ;
     RECT  17.712 27.877 19.464 27.925 ;
     RECT  16.656 27.925 19.464 30.037 ;
     RECT  16.56 30.037 19.464 30.085 ;
     RECT  16.464 30.085 19.464 30.132 ;
     RECT  16.488 30.132 16.56 30.16 ;
     RECT  16.584 30.132 16.656 30.16 ;
     RECT  16.68 30.132 16.752 30.16 ;
     RECT  16.776 30.132 16.848 30.16 ;
     RECT  16.872 30.132 16.944 30.16 ;
     RECT  16.968 30.132 17.04 30.16 ;
     RECT  17.064 30.132 17.136 30.16 ;
     RECT  17.16 30.132 17.232 30.16 ;
     RECT  17.256 30.132 17.328 30.16 ;
     RECT  17.352 30.132 17.424 30.16 ;
     RECT  17.448 30.132 17.52 30.16 ;
     RECT  17.544 30.132 17.616 30.16 ;
     RECT  17.64 30.132 17.712 30.16 ;
     RECT  17.736 30.132 17.808 30.16 ;
     RECT  17.832 30.132 17.904 30.16 ;
     RECT  17.928 30.132 18 30.16 ;
     RECT  18.024 30.132 18.096 30.16 ;
     RECT  18.12 30.132 18.192 30.16 ;
     RECT  18.216 30.132 18.288 30.16 ;
     RECT  18.312 30.132 18.384 30.16 ;
     RECT  18.408 30.132 18.48 30.16 ;
     RECT  18.504 30.132 18.576 30.16 ;
     RECT  18.6 30.132 18.672 30.16 ;
     RECT  18.696 30.132 18.768 30.16 ;
     RECT  18.792 30.132 18.864 30.16 ;
     RECT  18.888 30.132 18.96 30.16 ;
     RECT  18.984 30.132 19.056 30.16 ;
     RECT  19.08 30.132 19.152 30.16 ;
     RECT  19.176 30.132 19.248 30.16 ;
     RECT  19.272 30.132 19.344 30.16 ;
     RECT  19.368 30.132 19.44 30.16 ;
     RECT  39.936 27.833 39.96 30.179 ;
     RECT  62.616 6.899 62.664 7.909 ;
     RECT  62.52 9.395 62.616 10.741 ;
     RECT  24.408 10.213 25.488 10.307 ;
     RECT  25.512 10.213 26.7 11.941 ;
     RECT  24.312 10.307 25.488 15.925 ;
     RECT  46.92 11.413 48.192 12.227 ;
     RECT  38.568 11.941 40.032 11.989 ;
     RECT  38.808 11.989 40.032 12.563 ;
     RECT  61.488 12.323 61.536 12.469 ;
     RECT  60.264 12.469 61.536 13.525 ;
     RECT  38.568 12.563 40.032 14.773 ;
     RECT  21.612 13.093 22.896 13.715 ;
     RECT  22.92 13.093 24 13.715 ;
     RECT  60.36 13.525 61.536 13.573 ;
     RECT  42.768 13.667 42.9 14.773 ;
     RECT  17.544 14.197 18.6 15.827 ;
     RECT  32.412 14.389 33.792 14.915 ;
     RECT  33.816 14.389 34.8 14.915 ;
     RECT  38.76 14.773 40.032 20.099 ;
     RECT  43.32 15.301 44.448 16.595 ;
     RECT  60.36 15.443 61.8 17.125 ;
     RECT  17.256 15.827 18.6 18.709 ;
     RECT  24.312 15.925 25.344 18.949 ;
     RECT  49.416 16.933 50.592 17.507 ;
     RECT  60.36 17.125 61.44 17.605 ;
     RECT  51.312 17.461 52.512 18.181 ;
     RECT  48.612 17.507 50.592 17.651 ;
     RECT  48.612 17.651 51 18.757 ;
     RECT  27.012 18.179 27.864 18.373 ;
     RECT  43.56 18.181 44.976 19.043 ;
     RECT  51.312 18.181 52.416 19.235 ;
     RECT  27.012 18.373 28.464 18.611 ;
     RECT  52.44 18.467 53.7 19.235 ;
     RECT  42.768 18.563 42.9 18.997 ;
     RECT  48.612 18.757 49.584 19.571 ;
     RECT  49.608 18.757 51 19.571 ;
     RECT  54.12 18.851 54.456 19.237 ;
     RECT  41.4 18.997 42.9 20.293 ;
     RECT  51.312 19.235 53.7 20.629 ;
     RECT  54.12 19.237 55.248 19.909 ;
     RECT  55.272 19.237 56.4 21.347 ;
     RECT  16.212 19.283 17.232 21.299 ;
     RECT  59.832 19.333 61.056 20.389 ;
     RECT  17.256 19.523 18.6 20.725 ;
     RECT  54.264 19.909 55.248 21.301 ;
     RECT  48 20.051 48.3 21.205 ;
     RECT  24.312 20.099 25.344 20.819 ;
     RECT  37.812 20.099 37.944 21.493 ;
     RECT  41.832 20.293 42.9 21.155 ;
     RECT  40.512 20.339 41.808 21.155 ;
     RECT  58.896 20.339 59.1 21.637 ;
     RECT  59.832 20.389 60.96 21.541 ;
     RECT  51.312 20.629 53.04 20.677 ;
     RECT  51.312 20.677 52.416 21.299 ;
     RECT  52.536 20.771 53.7 21.299 ;
     RECT  32.412 21.109 33.504 21.683 ;
     RECT  33.528 21.109 34.8 21.683 ;
     RECT  40.512 21.155 42.9 22.069 ;
     RECT  16.212 21.299 17.472 23.987 ;
     RECT  51.312 21.299 53.7 21.781 ;
     RECT  5.412 21.301 6.768 25.763 ;
     RECT  6.792 21.301 7.8 21.397 ;
     RECT  55.032 21.347 56.4 21.637 ;
     RECT  47.904 21.395 48.3 22.453 ;
     RECT  48.612 21.637 49.824 22.115 ;
     RECT  55.032 21.637 56.016 22.451 ;
     RECT  56.712 21.637 57.744 22.067 ;
     RECT  57.768 21.637 59.1 22.067 ;
     RECT  60.072 21.683 61.2 22.931 ;
     RECT  52.008 21.781 53.7 22.165 ;
     RECT  54.012 22.067 55.008 24.853 ;
     RECT  56.712 22.067 59.1 22.741 ;
     RECT  40.968 22.069 42.9 22.597 ;
     RECT  48.612 22.115 50.112 22.117 ;
     RECT  49.032 22.117 50.112 22.355 ;
     RECT  62.112 22.163 62.568 23.269 ;
     RECT  52.008 22.165 53.52 22.355 ;
     RECT  48.612 22.355 50.112 23.459 ;
     RECT  6.792 22.451 7.8 25.763 ;
     RECT  55.032 22.451 56.4 25.139 ;
     RECT  46.056 22.453 47.088 22.595 ;
     RECT  47.112 22.453 48.3 22.643 ;
     RECT  45.912 22.595 47.088 22.643 ;
     RECT  40.968 22.597 42.096 22.787 ;
     RECT  43.752 22.741 44.976 22.979 ;
     RECT  56.712 22.741 58.128 23.459 ;
     RECT  40.728 22.787 42.096 23.267 ;
     RECT  35.64 22.789 37.008 24.371 ;
     RECT  59.88 22.931 61.2 23.269 ;
     RECT  13.512 23.267 13.656 24.373 ;
     RECT  40.512 23.267 42.096 24.373 ;
     RECT  59.88 23.269 60.912 24.563 ;
     RECT  48.612 23.459 49.032 24.277 ;
     RECT  56.712 23.459 59.1 23.893 ;
     RECT  3.624 23.845 4.992 24.371 ;
     RECT  25.128 23.893 26.256 25.669 ;
     RECT  57.576 23.893 59.1 24.563 ;
     RECT  16.212 23.987 17.616 24.035 ;
     RECT  43.212 24.131 43.464 25.573 ;
     RECT  35.64 24.371 37.056 24.467 ;
     RECT  40.632 24.373 42.096 24.421 ;
     RECT  40.728 24.421 42.096 24.853 ;
     RECT  59.88 24.563 60.96 25.139 ;
     RECT  22.488 24.757 24 26.101 ;
     RECT  40.728 24.853 41.952 25.141 ;
     RECT  59.412 25.139 60.96 25.763 ;
     RECT  37.812 25.283 39.36 25.811 ;
     RECT  30.36 25.523 30.456 26.773 ;
     RECT  25.272 25.669 26.256 26.291 ;
     RECT  45.912 25.717 46.992 26.819 ;
     RECT  47.016 25.717 48.3 26.819 ;
     RECT  59.412 25.763 59.544 26.485 ;
     RECT  37.812 25.811 39.936 26.725 ;
     RECT  40.92 26.003 42.192 26.387 ;
     RECT  23.016 26.101 24 26.915 ;
     RECT  27.012 26.101 28.512 27.395 ;
     RECT  25.272 26.291 26.4 26.723 ;
     RECT  21.612 26.531 22.992 26.915 ;
     RECT  25.176 26.723 26.4 27.395 ;
     RECT  38.76 26.725 39.936 27.635 ;
     RECT  30.84 26.773 32.1 26.915 ;
     RECT  19.464 27.781 20.976 27.923 ;
  END
END qfd_landh_128_EN_65x30
END LIBRARY
